VERSION 5.4 ;
NAMESCASESENSITIVE ON ;
BUSBITCHARS "[]" ;
DIVIDERCHAR "/" ;
UNITS
  DATABASE MICRONS 2000 ;
END UNITS
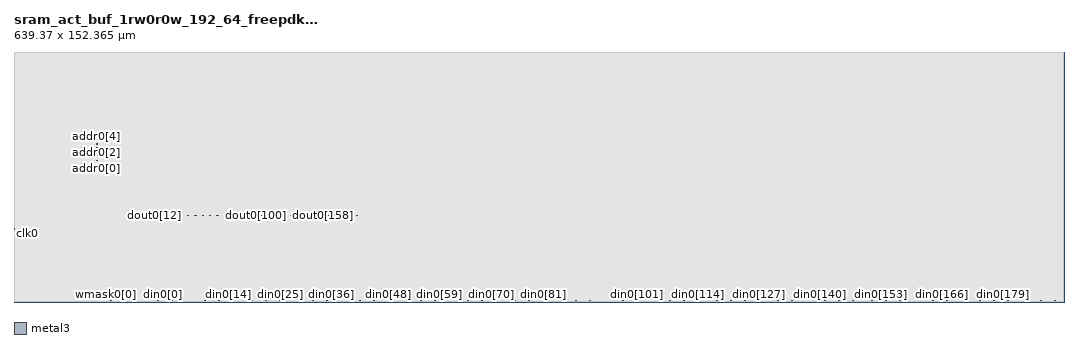
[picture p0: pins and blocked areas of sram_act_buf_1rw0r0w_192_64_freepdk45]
MACRO sram_act_buf_1rw0r0w_192_64_freepdk45
   CLASS BLOCK ;
   SIZE 639.37 BY 152.365 ;
   SYMMETRY X Y R90 ;
   PIN din0[0]
      DIRECTION INPUT ;
      PORT
         LAYER metal3 ;
         RECT  90.465 1.0375 90.6 1.1725 ;
      END
   END din0[0]
   PIN din0[1]
      DIRECTION INPUT ;
      PORT
         LAYER metal3 ;
         RECT  93.325 1.0375 93.46 1.1725 ;
      END
   END din0[1]
   PIN din0[2]
      DIRECTION INPUT ;
      PORT
         LAYER metal3 ;
         RECT  96.185 1.0375 96.32 1.1725 ;
      END
   END din0[2]
   PIN din0[3]
      DIRECTION INPUT ;
      PORT
         LAYER metal3 ;
         RECT  99.045 1.0375 99.18 1.1725 ;
      END
   END din0[3]
   PIN din0[4]
      DIRECTION INPUT ;
      PORT
         LAYER metal3 ;
         RECT  101.905 1.0375 102.04 1.1725 ;
      END
   END din0[4]
   PIN din0[5]
      DIRECTION INPUT ;
      PORT
         LAYER metal3 ;
         RECT  104.765 1.0375 104.9 1.1725 ;
      END
   END din0[5]
   PIN din0[6]
      DIRECTION INPUT ;
      PORT
         LAYER metal3 ;
         RECT  107.625 1.0375 107.76 1.1725 ;
      END
   END din0[6]
   PIN din0[7]
      DIRECTION INPUT ;
      PORT
         LAYER metal3 ;
         RECT  110.485 1.0375 110.62 1.1725 ;
      END
   END din0[7]
   PIN din0[8]
      DIRECTION INPUT ;
      PORT
         LAYER metal3 ;
         RECT  113.345 1.0375 113.48 1.1725 ;
      END
   END din0[8]
   PIN din0[9]
      DIRECTION INPUT ;
      PORT
         LAYER metal3 ;
         RECT  116.205 1.0375 116.34 1.1725 ;
      END
   END din0[9]
   PIN din0[10]
      DIRECTION INPUT ;
      PORT
         LAYER metal3 ;
         RECT  119.065 1.0375 119.2 1.1725 ;
      END
   END din0[10]
   PIN din0[11]
      DIRECTION INPUT ;
      PORT
         LAYER metal3 ;
         RECT  121.925 1.0375 122.06 1.1725 ;
      END
   END din0[11]
   PIN din0[12]
      DIRECTION INPUT ;
      PORT
         LAYER metal3 ;
         RECT  124.785 1.0375 124.92 1.1725 ;
      END
   END din0[12]
   PIN din0[13]
      DIRECTION INPUT ;
      PORT
         LAYER metal3 ;
         RECT  127.645 1.0375 127.78 1.1725 ;
      END
   END din0[13]
   PIN din0[14]
      DIRECTION INPUT ;
      PORT
         LAYER metal3 ;
         RECT  130.505 1.0375 130.64 1.1725 ;
      END
   END din0[14]
   PIN din0[15]
      DIRECTION INPUT ;
      PORT
         LAYER metal3 ;
         RECT  133.365 1.0375 133.5 1.1725 ;
      END
   END din0[15]
   PIN din0[16]
      DIRECTION INPUT ;
      PORT
         LAYER metal3 ;
         RECT  136.225 1.0375 136.36 1.1725 ;
      END
   END din0[16]
   PIN din0[17]
      DIRECTION INPUT ;
      PORT
         LAYER metal3 ;
         RECT  139.085 1.0375 139.22 1.1725 ;
      END
   END din0[17]
   PIN din0[18]
      DIRECTION INPUT ;
      PORT
         LAYER metal3 ;
         RECT  141.945 1.0375 142.08 1.1725 ;
      END
   END din0[18]
   PIN din0[19]
      DIRECTION INPUT ;
      PORT
         LAYER metal3 ;
         RECT  144.805 1.0375 144.94 1.1725 ;
      END
   END din0[19]
   PIN din0[20]
      DIRECTION INPUT ;
      PORT
         LAYER metal3 ;
         RECT  147.665 1.0375 147.8 1.1725 ;
      END
   END din0[20]
   PIN din0[21]
      DIRECTION INPUT ;
      PORT
         LAYER metal3 ;
         RECT  150.525 1.0375 150.66 1.1725 ;
      END
   END din0[21]
   PIN din0[22]
      DIRECTION INPUT ;
      PORT
         LAYER metal3 ;
         RECT  153.385 1.0375 153.52 1.1725 ;
      END
   END din0[22]
   PIN din0[23]
      DIRECTION INPUT ;
      PORT
         LAYER metal3 ;
         RECT  156.245 1.0375 156.38 1.1725 ;
      END
   END din0[23]
   PIN din0[24]
      DIRECTION INPUT ;
      PORT
         LAYER metal3 ;
         RECT  159.105 1.0375 159.24 1.1725 ;
      END
   END din0[24]
   PIN din0[25]
      DIRECTION INPUT ;
      PORT
         LAYER metal3 ;
         RECT  161.965 1.0375 162.1 1.1725 ;
      END
   END din0[25]
   PIN din0[26]
      DIRECTION INPUT ;
      PORT
         LAYER metal3 ;
         RECT  164.825 1.0375 164.96 1.1725 ;
      END
   END din0[26]
   PIN din0[27]
      DIRECTION INPUT ;
      PORT
         LAYER metal3 ;
         RECT  167.685 1.0375 167.82 1.1725 ;
      END
   END din0[27]
   PIN din0[28]
      DIRECTION INPUT ;
      PORT
         LAYER metal3 ;
         RECT  170.545 1.0375 170.68 1.1725 ;
      END
   END din0[28]
   PIN din0[29]
      DIRECTION INPUT ;
      PORT
         LAYER metal3 ;
         RECT  173.405 1.0375 173.54 1.1725 ;
      END
   END din0[29]
   PIN din0[30]
      DIRECTION INPUT ;
      PORT
         LAYER metal3 ;
         RECT  176.265 1.0375 176.4 1.1725 ;
      END
   END din0[30]
   PIN din0[31]
      DIRECTION INPUT ;
      PORT
         LAYER metal3 ;
         RECT  179.125 1.0375 179.26 1.1725 ;
      END
   END din0[31]
   PIN din0[32]
      DIRECTION INPUT ;
      PORT
         LAYER metal3 ;
         RECT  181.985 1.0375 182.12 1.1725 ;
      END
   END din0[32]
   PIN din0[33]
      DIRECTION INPUT ;
      PORT
         LAYER metal3 ;
         RECT  184.845 1.0375 184.98 1.1725 ;
      END
   END din0[33]
   PIN din0[34]
      DIRECTION INPUT ;
      PORT
         LAYER metal3 ;
         RECT  187.705 1.0375 187.84 1.1725 ;
      END
   END din0[34]
   PIN din0[35]
      DIRECTION INPUT ;
      PORT
         LAYER metal3 ;
         RECT  190.565 1.0375 190.7 1.1725 ;
      END
   END din0[35]
   PIN din0[36]
      DIRECTION INPUT ;
      PORT
         LAYER metal3 ;
         RECT  193.425 1.0375 193.56 1.1725 ;
      END
   END din0[36]
   PIN din0[37]
      DIRECTION INPUT ;
      PORT
         LAYER metal3 ;
         RECT  196.285 1.0375 196.42 1.1725 ;
      END
   END din0[37]
   PIN din0[38]
      DIRECTION INPUT ;
      PORT
         LAYER metal3 ;
         RECT  199.145 1.0375 199.28 1.1725 ;
      END
   END din0[38]
   PIN din0[39]
      DIRECTION INPUT ;
      PORT
         LAYER metal3 ;
         RECT  202.005 1.0375 202.14 1.1725 ;
      END
   END din0[39]
   PIN din0[40]
      DIRECTION INPUT ;
      PORT
         LAYER metal3 ;
         RECT  204.865 1.0375 205.0 1.1725 ;
      END
   END din0[40]
   PIN din0[41]
      DIRECTION INPUT ;
      PORT
         LAYER metal3 ;
         RECT  207.725 1.0375 207.86 1.1725 ;
      END
   END din0[41]
   PIN din0[42]
      DIRECTION INPUT ;
      PORT
         LAYER metal3 ;
         RECT  210.585 1.0375 210.72 1.1725 ;
      END
   END din0[42]
   PIN din0[43]
      DIRECTION INPUT ;
      PORT
         LAYER metal3 ;
         RECT  213.445 1.0375 213.58 1.1725 ;
      END
   END din0[43]
   PIN din0[44]
      DIRECTION INPUT ;
      PORT
         LAYER metal3 ;
         RECT  216.305 1.0375 216.44 1.1725 ;
      END
   END din0[44]
   PIN din0[45]
      DIRECTION INPUT ;
      PORT
         LAYER metal3 ;
         RECT  219.165 1.0375 219.3 1.1725 ;
      END
   END din0[45]
   PIN din0[46]
      DIRECTION INPUT ;
      PORT
         LAYER metal3 ;
         RECT  222.025 1.0375 222.16 1.1725 ;
      END
   END din0[46]
   PIN din0[47]
      DIRECTION INPUT ;
      PORT
         LAYER metal3 ;
         RECT  224.885 1.0375 225.02 1.1725 ;
      END
   END din0[47]
   PIN din0[48]
      DIRECTION INPUT ;
      PORT
         LAYER metal3 ;
         RECT  227.745 1.0375 227.88 1.1725 ;
      END
   END din0[48]
   PIN din0[49]
      DIRECTION INPUT ;
      PORT
         LAYER metal3 ;
         RECT  230.605 1.0375 230.74 1.1725 ;
      END
   END din0[49]
   PIN din0[50]
      DIRECTION INPUT ;
      PORT
         LAYER metal3 ;
         RECT  233.465 1.0375 233.6 1.1725 ;
      END
   END din0[50]
   PIN din0[51]
      DIRECTION INPUT ;
      PORT
         LAYER metal3 ;
         RECT  236.325 1.0375 236.46 1.1725 ;
      END
   END din0[51]
   PIN din0[52]
      DIRECTION INPUT ;
      PORT
         LAYER metal3 ;
         RECT  239.185 1.0375 239.32 1.1725 ;
      END
   END din0[52]
   PIN din0[53]
      DIRECTION INPUT ;
      PORT
         LAYER metal3 ;
         RECT  242.045 1.0375 242.18 1.1725 ;
      END
   END din0[53]
   PIN din0[54]
      DIRECTION INPUT ;
      PORT
         LAYER metal3 ;
         RECT  244.905 1.0375 245.04 1.1725 ;
      END
   END din0[54]
   PIN din0[55]
      DIRECTION INPUT ;
      PORT
         LAYER metal3 ;
         RECT  247.765 1.0375 247.9 1.1725 ;
      END
   END din0[55]
   PIN din0[56]
      DIRECTION INPUT ;
      PORT
         LAYER metal3 ;
         RECT  250.625 1.0375 250.76 1.1725 ;
      END
   END din0[56]
   PIN din0[57]
      DIRECTION INPUT ;
      PORT
         LAYER metal3 ;
         RECT  253.485 1.0375 253.62 1.1725 ;
      END
   END din0[57]
   PIN din0[58]
      DIRECTION INPUT ;
      PORT
         LAYER metal3 ;
         RECT  256.345 1.0375 256.48 1.1725 ;
      END
   END din0[58]
   PIN din0[59]
      DIRECTION INPUT ;
      PORT
         LAYER metal3 ;
         RECT  259.205 1.0375 259.34 1.1725 ;
      END
   END din0[59]
   PIN din0[60]
      DIRECTION INPUT ;
      PORT
         LAYER metal3 ;
         RECT  262.065 1.0375 262.2 1.1725 ;
      END
   END din0[60]
   PIN din0[61]
      DIRECTION INPUT ;
      PORT
         LAYER metal3 ;
         RECT  264.925 1.0375 265.06 1.1725 ;
      END
   END din0[61]
   PIN din0[62]
      DIRECTION INPUT ;
      PORT
         LAYER metal3 ;
         RECT  267.785 1.0375 267.92 1.1725 ;
      END
   END din0[62]
   PIN din0[63]
      DIRECTION INPUT ;
      PORT
         LAYER metal3 ;
         RECT  270.645 1.0375 270.78 1.1725 ;
      END
   END din0[63]
   PIN din0[64]
      DIRECTION INPUT ;
      PORT
         LAYER metal3 ;
         RECT  273.505 1.0375 273.64 1.1725 ;
      END
   END din0[64]
   PIN din0[65]
      DIRECTION INPUT ;
      PORT
         LAYER metal3 ;
         RECT  276.365 1.0375 276.5 1.1725 ;
      END
   END din0[65]
   PIN din0[66]
      DIRECTION INPUT ;
      PORT
         LAYER metal3 ;
         RECT  279.225 1.0375 279.36 1.1725 ;
      END
   END din0[66]
   PIN din0[67]
      DIRECTION INPUT ;
      PORT
         LAYER metal3 ;
         RECT  282.085 1.0375 282.22 1.1725 ;
      END
   END din0[67]
   PIN din0[68]
      DIRECTION INPUT ;
      PORT
         LAYER metal3 ;
         RECT  284.945 1.0375 285.08 1.1725 ;
      END
   END din0[68]
   PIN din0[69]
      DIRECTION INPUT ;
      PORT
         LAYER metal3 ;
         RECT  287.805 1.0375 287.94 1.1725 ;
      END
   END din0[69]
   PIN din0[70]
      DIRECTION INPUT ;
      PORT
         LAYER metal3 ;
         RECT  290.665 1.0375 290.8 1.1725 ;
      END
   END din0[70]
   PIN din0[71]
      DIRECTION INPUT ;
      PORT
         LAYER metal3 ;
         RECT  293.525 1.0375 293.66 1.1725 ;
      END
   END din0[71]
   PIN din0[72]
      DIRECTION INPUT ;
      PORT
         LAYER metal3 ;
         RECT  296.385 1.0375 296.52 1.1725 ;
      END
   END din0[72]
   PIN din0[73]
      DIRECTION INPUT ;
      PORT
         LAYER metal3 ;
         RECT  299.245 1.0375 299.38 1.1725 ;
      END
   END din0[73]
   PIN din0[74]
      DIRECTION INPUT ;
      PORT
         LAYER metal3 ;
         RECT  302.105 1.0375 302.24 1.1725 ;
      END
   END din0[74]
   PIN din0[75]
      DIRECTION INPUT ;
      PORT
         LAYER metal3 ;
         RECT  304.965 1.0375 305.1 1.1725 ;
      END
   END din0[75]
   PIN din0[76]
      DIRECTION INPUT ;
      PORT
         LAYER metal3 ;
         RECT  307.825 1.0375 307.96 1.1725 ;
      END
   END din0[76]
   PIN din0[77]
      DIRECTION INPUT ;
      PORT
         LAYER metal3 ;
         RECT  310.685 1.0375 310.82 1.1725 ;
      END
   END din0[77]
   PIN din0[78]
      DIRECTION INPUT ;
      PORT
         LAYER metal3 ;
         RECT  313.545 1.0375 313.68 1.1725 ;
      END
   END din0[78]
   PIN din0[79]
      DIRECTION INPUT ;
      PORT
         LAYER metal3 ;
         RECT  316.405 1.0375 316.54 1.1725 ;
      END
   END din0[79]
   PIN din0[80]
      DIRECTION INPUT ;
      PORT
         LAYER metal3 ;
         RECT  319.265 1.0375 319.4 1.1725 ;
      END
   END din0[80]
   PIN din0[81]
      DIRECTION INPUT ;
      PORT
         LAYER metal3 ;
         RECT  322.125 1.0375 322.26 1.1725 ;
      END
   END din0[81]
   PIN din0[82]
      DIRECTION INPUT ;
      PORT
         LAYER metal3 ;
         RECT  324.985 1.0375 325.12 1.1725 ;
      END
   END din0[82]
   PIN din0[83]
      DIRECTION INPUT ;
      PORT
         LAYER metal3 ;
         RECT  327.845 1.0375 327.98 1.1725 ;
      END
   END din0[83]
   PIN din0[84]
      DIRECTION INPUT ;
      PORT
         LAYER metal3 ;
         RECT  330.705 1.0375 330.84 1.1725 ;
      END
   END din0[84]
   PIN din0[85]
      DIRECTION INPUT ;
      PORT
         LAYER metal3 ;
         RECT  333.565 1.0375 333.7 1.1725 ;
      END
   END din0[85]
   PIN din0[86]
      DIRECTION INPUT ;
      PORT
         LAYER metal3 ;
         RECT  336.425 1.0375 336.56 1.1725 ;
      END
   END din0[86]
   PIN din0[87]
      DIRECTION INPUT ;
      PORT
         LAYER metal3 ;
         RECT  339.285 1.0375 339.42 1.1725 ;
      END
   END din0[87]
   PIN din0[88]
      DIRECTION INPUT ;
      PORT
         LAYER metal3 ;
         RECT  342.145 1.0375 342.28 1.1725 ;
      END
   END din0[88]
   PIN din0[89]
      DIRECTION INPUT ;
      PORT
         LAYER metal3 ;
         RECT  345.005 1.0375 345.14 1.1725 ;
      END
   END din0[89]
   PIN din0[90]
      DIRECTION INPUT ;
      PORT
         LAYER metal3 ;
         RECT  347.865 1.0375 348.0 1.1725 ;
      END
   END din0[90]
   PIN din0[91]
      DIRECTION INPUT ;
      PORT
         LAYER metal3 ;
         RECT  350.725 1.0375 350.86 1.1725 ;
      END
   END din0[91]
   PIN din0[92]
      DIRECTION INPUT ;
      PORT
         LAYER metal3 ;
         RECT  353.585 1.0375 353.72 1.1725 ;
      END
   END din0[92]
   PIN din0[93]
      DIRECTION INPUT ;
      PORT
         LAYER metal3 ;
         RECT  356.445 1.0375 356.58 1.1725 ;
      END
   END din0[93]
   PIN din0[94]
      DIRECTION INPUT ;
      PORT
         LAYER metal3 ;
         RECT  359.305 1.0375 359.44 1.1725 ;
      END
   END din0[94]
   PIN din0[95]
      DIRECTION INPUT ;
      PORT
         LAYER metal3 ;
         RECT  362.165 1.0375 362.3 1.1725 ;
      END
   END din0[95]
   PIN din0[96]
      DIRECTION INPUT ;
      PORT
         LAYER metal3 ;
         RECT  365.025 1.0375 365.16 1.1725 ;
      END
   END din0[96]
   PIN din0[97]
      DIRECTION INPUT ;
      PORT
         LAYER metal3 ;
         RECT  367.885 1.0375 368.02 1.1725 ;
      END
   END din0[97]
   PIN din0[98]
      DIRECTION INPUT ;
      PORT
         LAYER metal3 ;
         RECT  370.745 1.0375 370.88 1.1725 ;
      END
   END din0[98]
   PIN din0[99]
      DIRECTION INPUT ;
      PORT
         LAYER metal3 ;
         RECT  373.605 1.0375 373.74 1.1725 ;
      END
   END din0[99]
   PIN din0[100]
      DIRECTION INPUT ;
      PORT
         LAYER metal3 ;
         RECT  376.465 1.0375 376.6 1.1725 ;
      END
   END din0[100]
   PIN din0[101]
      DIRECTION INPUT ;
      PORT
         LAYER metal3 ;
         RECT  379.325 1.0375 379.46 1.1725 ;
      END
   END din0[101]
   PIN din0[102]
      DIRECTION INPUT ;
      PORT
         LAYER metal3 ;
         RECT  382.185 1.0375 382.32 1.1725 ;
      END
   END din0[102]
   PIN din0[103]
      DIRECTION INPUT ;
      PORT
         LAYER metal3 ;
         RECT  385.045 1.0375 385.18 1.1725 ;
      END
   END din0[103]
   PIN din0[104]
      DIRECTION INPUT ;
      PORT
         LAYER metal3 ;
         RECT  387.905 1.0375 388.04 1.1725 ;
      END
   END din0[104]
   PIN din0[105]
      DIRECTION INPUT ;
      PORT
         LAYER metal3 ;
         RECT  390.765 1.0375 390.9 1.1725 ;
      END
   END din0[105]
   PIN din0[106]
      DIRECTION INPUT ;
      PORT
         LAYER metal3 ;
         RECT  393.625 1.0375 393.76 1.1725 ;
      END
   END din0[106]
   PIN din0[107]
      DIRECTION INPUT ;
      PORT
         LAYER metal3 ;
         RECT  396.485 1.0375 396.62 1.1725 ;
      END
   END din0[107]
   PIN din0[108]
      DIRECTION INPUT ;
      PORT
         LAYER metal3 ;
         RECT  399.345 1.0375 399.48 1.1725 ;
      END
   END din0[108]
   PIN din0[109]
      DIRECTION INPUT ;
      PORT
         LAYER metal3 ;
         RECT  402.205 1.0375 402.34 1.1725 ;
      END
   END din0[109]
   PIN din0[110]
      DIRECTION INPUT ;
      PORT
         LAYER metal3 ;
         RECT  405.065 1.0375 405.2 1.1725 ;
      END
   END din0[110]
   PIN din0[111]
      DIRECTION INPUT ;
      PORT
         LAYER metal3 ;
         RECT  407.925 1.0375 408.06 1.1725 ;
      END
   END din0[111]
   PIN din0[112]
      DIRECTION INPUT ;
      PORT
         LAYER metal3 ;
         RECT  410.785 1.0375 410.92 1.1725 ;
      END
   END din0[112]
   PIN din0[113]
      DIRECTION INPUT ;
      PORT
         LAYER metal3 ;
         RECT  413.645 1.0375 413.78 1.1725 ;
      END
   END din0[113]
   PIN din0[114]
      DIRECTION INPUT ;
      PORT
         LAYER metal3 ;
         RECT  416.505 1.0375 416.64 1.1725 ;
      END
   END din0[114]
   PIN din0[115]
      DIRECTION INPUT ;
      PORT
         LAYER metal3 ;
         RECT  419.365 1.0375 419.5 1.1725 ;
      END
   END din0[115]
   PIN din0[116]
      DIRECTION INPUT ;
      PORT
         LAYER metal3 ;
         RECT  422.225 1.0375 422.36 1.1725 ;
      END
   END din0[116]
   PIN din0[117]
      DIRECTION INPUT ;
      PORT
         LAYER metal3 ;
         RECT  425.085 1.0375 425.22 1.1725 ;
      END
   END din0[117]
   PIN din0[118]
      DIRECTION INPUT ;
      PORT
         LAYER metal3 ;
         RECT  427.945 1.0375 428.08 1.1725 ;
      END
   END din0[118]
   PIN din0[119]
      DIRECTION INPUT ;
      PORT
         LAYER metal3 ;
         RECT  430.805 1.0375 430.94 1.1725 ;
      END
   END din0[119]
   PIN din0[120]
      DIRECTION INPUT ;
      PORT
         LAYER metal3 ;
         RECT  433.665 1.0375 433.8 1.1725 ;
      END
   END din0[120]
   PIN din0[121]
      DIRECTION INPUT ;
      PORT
         LAYER metal3 ;
         RECT  436.525 1.0375 436.66 1.1725 ;
      END
   END din0[121]
   PIN din0[122]
      DIRECTION INPUT ;
      PORT
         LAYER metal3 ;
         RECT  439.385 1.0375 439.52 1.1725 ;
      END
   END din0[122]
   PIN din0[123]
      DIRECTION INPUT ;
      PORT
         LAYER metal3 ;
         RECT  442.245 1.0375 442.38 1.1725 ;
      END
   END din0[123]
   PIN din0[124]
      DIRECTION INPUT ;
      PORT
         LAYER metal3 ;
         RECT  445.105 1.0375 445.24 1.1725 ;
      END
   END din0[124]
   PIN din0[125]
      DIRECTION INPUT ;
      PORT
         LAYER metal3 ;
         RECT  447.965 1.0375 448.1 1.1725 ;
      END
   END din0[125]
   PIN din0[126]
      DIRECTION INPUT ;
      PORT
         LAYER metal3 ;
         RECT  450.825 1.0375 450.96 1.1725 ;
      END
   END din0[126]
   PIN din0[127]
      DIRECTION INPUT ;
      PORT
         LAYER metal3 ;
         RECT  453.685 1.0375 453.82 1.1725 ;
      END
   END din0[127]
   PIN din0[128]
      DIRECTION INPUT ;
      PORT
         LAYER metal3 ;
         RECT  456.545 1.0375 456.68 1.1725 ;
      END
   END din0[128]
   PIN din0[129]
      DIRECTION INPUT ;
      PORT
         LAYER metal3 ;
         RECT  459.405 1.0375 459.54 1.1725 ;
      END
   END din0[129]
   PIN din0[130]
      DIRECTION INPUT ;
      PORT
         LAYER metal3 ;
         RECT  462.265 1.0375 462.4 1.1725 ;
      END
   END din0[130]
   PIN din0[131]
      DIRECTION INPUT ;
      PORT
         LAYER metal3 ;
         RECT  465.125 1.0375 465.26 1.1725 ;
      END
   END din0[131]
   PIN din0[132]
      DIRECTION INPUT ;
      PORT
         LAYER metal3 ;
         RECT  467.985 1.0375 468.12 1.1725 ;
      END
   END din0[132]
   PIN din0[133]
      DIRECTION INPUT ;
      PORT
         LAYER metal3 ;
         RECT  470.845 1.0375 470.98 1.1725 ;
      END
   END din0[133]
   PIN din0[134]
      DIRECTION INPUT ;
      PORT
         LAYER metal3 ;
         RECT  473.705 1.0375 473.84 1.1725 ;
      END
   END din0[134]
   PIN din0[135]
      DIRECTION INPUT ;
      PORT
         LAYER metal3 ;
         RECT  476.565 1.0375 476.7 1.1725 ;
      END
   END din0[135]
   PIN din0[136]
      DIRECTION INPUT ;
      PORT
         LAYER metal3 ;
         RECT  479.425 1.0375 479.56 1.1725 ;
      END
   END din0[136]
   PIN din0[137]
      DIRECTION INPUT ;
      PORT
         LAYER metal3 ;
         RECT  482.285 1.0375 482.42 1.1725 ;
      END
   END din0[137]
   PIN din0[138]
      DIRECTION INPUT ;
      PORT
         LAYER metal3 ;
         RECT  485.145 1.0375 485.28 1.1725 ;
      END
   END din0[138]
   PIN din0[139]
      DIRECTION INPUT ;
      PORT
         LAYER metal3 ;
         RECT  488.005 1.0375 488.14 1.1725 ;
      END
   END din0[139]
   PIN din0[140]
      DIRECTION INPUT ;
      PORT
         LAYER metal3 ;
         RECT  490.865 1.0375 491.0 1.1725 ;
      END
   END din0[140]
   PIN din0[141]
      DIRECTION INPUT ;
      PORT
         LAYER metal3 ;
         RECT  493.725 1.0375 493.86 1.1725 ;
      END
   END din0[141]
   PIN din0[142]
      DIRECTION INPUT ;
      PORT
         LAYER metal3 ;
         RECT  496.585 1.0375 496.72 1.1725 ;
      END
   END din0[142]
   PIN din0[143]
      DIRECTION INPUT ;
      PORT
         LAYER metal3 ;
         RECT  499.445 1.0375 499.58 1.1725 ;
      END
   END din0[143]
   PIN din0[144]
      DIRECTION INPUT ;
      PORT
         LAYER metal3 ;
         RECT  502.305 1.0375 502.44 1.1725 ;
      END
   END din0[144]
   PIN din0[145]
      DIRECTION INPUT ;
      PORT
         LAYER metal3 ;
         RECT  505.165 1.0375 505.3 1.1725 ;
      END
   END din0[145]
   PIN din0[146]
      DIRECTION INPUT ;
      PORT
         LAYER metal3 ;
         RECT  508.025 1.0375 508.16 1.1725 ;
      END
   END din0[146]
   PIN din0[147]
      DIRECTION INPUT ;
      PORT
         LAYER metal3 ;
         RECT  510.885 1.0375 511.02 1.1725 ;
      END
   END din0[147]
   PIN din0[148]
      DIRECTION INPUT ;
      PORT
         LAYER metal3 ;
         RECT  513.745 1.0375 513.88 1.1725 ;
      END
   END din0[148]
   PIN din0[149]
      DIRECTION INPUT ;
      PORT
         LAYER metal3 ;
         RECT  516.605 1.0375 516.74 1.1725 ;
      END
   END din0[149]
   PIN din0[150]
      DIRECTION INPUT ;
      PORT
         LAYER metal3 ;
         RECT  519.465 1.0375 519.6 1.1725 ;
      END
   END din0[150]
   PIN din0[151]
      DIRECTION INPUT ;
      PORT
         LAYER metal3 ;
         RECT  522.325 1.0375 522.46 1.1725 ;
      END
   END din0[151]
   PIN din0[152]
      DIRECTION INPUT ;
      PORT
         LAYER metal3 ;
         RECT  525.185 1.0375 525.32 1.1725 ;
      END
   END din0[152]
   PIN din0[153]
      DIRECTION INPUT ;
      PORT
         LAYER metal3 ;
         RECT  528.045 1.0375 528.18 1.1725 ;
      END
   END din0[153]
   PIN din0[154]
      DIRECTION INPUT ;
      PORT
         LAYER metal3 ;
         RECT  530.905 1.0375 531.04 1.1725 ;
      END
   END din0[154]
   PIN din0[155]
      DIRECTION INPUT ;
      PORT
         LAYER metal3 ;
         RECT  533.765 1.0375 533.9 1.1725 ;
      END
   END din0[155]
   PIN din0[156]
      DIRECTION INPUT ;
      PORT
         LAYER metal3 ;
         RECT  536.625 1.0375 536.76 1.1725 ;
      END
   END din0[156]
   PIN din0[157]
      DIRECTION INPUT ;
      PORT
         LAYER metal3 ;
         RECT  539.485 1.0375 539.62 1.1725 ;
      END
   END din0[157]
   PIN din0[158]
      DIRECTION INPUT ;
      PORT
         LAYER metal3 ;
         RECT  542.345 1.0375 542.48 1.1725 ;
      END
   END din0[158]
   PIN din0[159]
      DIRECTION INPUT ;
      PORT
         LAYER metal3 ;
         RECT  545.205 1.0375 545.34 1.1725 ;
      END
   END din0[159]
   PIN din0[160]
      DIRECTION INPUT ;
      PORT
         LAYER metal3 ;
         RECT  548.065 1.0375 548.2 1.1725 ;
      END
   END din0[160]
   PIN din0[161]
      DIRECTION INPUT ;
      PORT
         LAYER metal3 ;
         RECT  550.925 1.0375 551.06 1.1725 ;
      END
   END din0[161]
   PIN din0[162]
      DIRECTION INPUT ;
      PORT
         LAYER metal3 ;
         RECT  553.785 1.0375 553.92 1.1725 ;
      END
   END din0[162]
   PIN din0[163]
      DIRECTION INPUT ;
      PORT
         LAYER metal3 ;
         RECT  556.645 1.0375 556.78 1.1725 ;
      END
   END din0[163]
   PIN din0[164]
      DIRECTION INPUT ;
      PORT
         LAYER metal3 ;
         RECT  559.505 1.0375 559.64 1.1725 ;
      END
   END din0[164]
   PIN din0[165]
      DIRECTION INPUT ;
      PORT
         LAYER metal3 ;
         RECT  562.365 1.0375 562.5 1.1725 ;
      END
   END din0[165]
   PIN din0[166]
      DIRECTION INPUT ;
      PORT
         LAYER metal3 ;
         RECT  565.225 1.0375 565.36 1.1725 ;
      END
   END din0[166]
   PIN din0[167]
      DIRECTION INPUT ;
      PORT
         LAYER metal3 ;
         RECT  568.085 1.0375 568.22 1.1725 ;
      END
   END din0[167]
   PIN din0[168]
      DIRECTION INPUT ;
      PORT
         LAYER metal3 ;
         RECT  570.945 1.0375 571.08 1.1725 ;
      END
   END din0[168]
   PIN din0[169]
      DIRECTION INPUT ;
      PORT
         LAYER metal3 ;
         RECT  573.805 1.0375 573.94 1.1725 ;
      END
   END din0[169]
   PIN din0[170]
      DIRECTION INPUT ;
      PORT
         LAYER metal3 ;
         RECT  576.665 1.0375 576.8 1.1725 ;
      END
   END din0[170]
   PIN din0[171]
      DIRECTION INPUT ;
      PORT
         LAYER metal3 ;
         RECT  579.525 1.0375 579.66 1.1725 ;
      END
   END din0[171]
   PIN din0[172]
      DIRECTION INPUT ;
      PORT
         LAYER metal3 ;
         RECT  582.385 1.0375 582.52 1.1725 ;
      END
   END din0[172]
   PIN din0[173]
      DIRECTION INPUT ;
      PORT
         LAYER metal3 ;
         RECT  585.245 1.0375 585.38 1.1725 ;
      END
   END din0[173]
   PIN din0[174]
      DIRECTION INPUT ;
      PORT
         LAYER metal3 ;
         RECT  588.105 1.0375 588.24 1.1725 ;
      END
   END din0[174]
   PIN din0[175]
      DIRECTION INPUT ;
      PORT
         LAYER metal3 ;
         RECT  590.965 1.0375 591.1 1.1725 ;
      END
   END din0[175]
   PIN din0[176]
      DIRECTION INPUT ;
      PORT
         LAYER metal3 ;
         RECT  593.825 1.0375 593.96 1.1725 ;
      END
   END din0[176]
   PIN din0[177]
      DIRECTION INPUT ;
      PORT
         LAYER metal3 ;
         RECT  596.685 1.0375 596.82 1.1725 ;
      END
   END din0[177]
   PIN din0[178]
      DIRECTION INPUT ;
      PORT
         LAYER metal3 ;
         RECT  599.545 1.0375 599.68 1.1725 ;
      END
   END din0[178]
   PIN din0[179]
      DIRECTION INPUT ;
      PORT
         LAYER metal3 ;
         RECT  602.405 1.0375 602.54 1.1725 ;
      END
   END din0[179]
   PIN din0[180]
      DIRECTION INPUT ;
      PORT
         LAYER metal3 ;
         RECT  605.265 1.0375 605.4 1.1725 ;
      END
   END din0[180]
   PIN din0[181]
      DIRECTION INPUT ;
      PORT
         LAYER metal3 ;
         RECT  608.125 1.0375 608.26 1.1725 ;
      END
   END din0[181]
   PIN din0[182]
      DIRECTION INPUT ;
      PORT
         LAYER metal3 ;
         RECT  610.985 1.0375 611.12 1.1725 ;
      END
   END din0[182]
   PIN din0[183]
      DIRECTION INPUT ;
      PORT
         LAYER metal3 ;
         RECT  613.845 1.0375 613.98 1.1725 ;
      END
   END din0[183]
   PIN din0[184]
      DIRECTION INPUT ;
      PORT
         LAYER metal3 ;
         RECT  616.705 1.0375 616.84 1.1725 ;
      END
   END din0[184]
   PIN din0[185]
      DIRECTION INPUT ;
      PORT
         LAYER metal3 ;
         RECT  619.565 1.0375 619.7 1.1725 ;
      END
   END din0[185]
   PIN din0[186]
      DIRECTION INPUT ;
      PORT
         LAYER metal3 ;
         RECT  622.425 1.0375 622.56 1.1725 ;
      END
   END din0[186]
   PIN din0[187]
      DIRECTION INPUT ;
      PORT
         LAYER metal3 ;
         RECT  625.285 1.0375 625.42 1.1725 ;
      END
   END din0[187]
   PIN din0[188]
      DIRECTION INPUT ;
      PORT
         LAYER metal3 ;
         RECT  628.145 1.0375 628.28 1.1725 ;
      END
   END din0[188]
   PIN din0[189]
      DIRECTION INPUT ;
      PORT
         LAYER metal3 ;
         RECT  631.005 1.0375 631.14 1.1725 ;
      END
   END din0[189]
   PIN din0[190]
      DIRECTION INPUT ;
      PORT
         LAYER metal3 ;
         RECT  633.865 1.0375 634.0 1.1725 ;
      END
   END din0[190]
   PIN din0[191]
      DIRECTION INPUT ;
      PORT
         LAYER metal3 ;
         RECT  636.725 1.0375 636.86 1.1725 ;
      END
   END din0[191]
   PIN addr0[0]
      DIRECTION INPUT ;
      PORT
         LAYER metal3 ;
         RECT  50.425 86.32 50.56 86.455 ;
      END
   END addr0[0]
   PIN addr0[1]
      DIRECTION INPUT ;
      PORT
         LAYER metal3 ;
         RECT  50.425 89.05 50.56 89.185 ;
      END
   END addr0[1]
   PIN addr0[2]
      DIRECTION INPUT ;
      PORT
         LAYER metal3 ;
         RECT  50.425 91.26 50.56 91.395 ;
      END
   END addr0[2]
   PIN addr0[3]
      DIRECTION INPUT ;
      PORT
         LAYER metal3 ;
         RECT  50.425 93.99 50.56 94.125 ;
      END
   END addr0[3]
   PIN addr0[4]
      DIRECTION INPUT ;
      PORT
         LAYER metal3 ;
         RECT  50.425 96.2 50.56 96.335 ;
      END
   END addr0[4]
   PIN addr0[5]
      DIRECTION INPUT ;
      PORT
         LAYER metal3 ;
         RECT  50.425 98.93 50.56 99.065 ;
      END
   END addr0[5]
   PIN csb0
      DIRECTION INPUT ;
      PORT
         LAYER metal3 ;
         RECT  0.285 41.6 0.42 41.735 ;
      END
   END csb0
   PIN web0
      DIRECTION INPUT ;
      PORT
         LAYER metal3 ;
         RECT  0.285 44.33 0.42 44.465 ;
      END
   END web0
   PIN clk0
      DIRECTION INPUT ;
      PORT
         LAYER metal3 ;
         RECT  6.5275 41.685 6.6625 41.82 ;
      END
   END clk0
   PIN wmask0[0]
      DIRECTION INPUT ;
      PORT
         LAYER metal3 ;
         RECT  56.145 1.0375 56.28 1.1725 ;
      END
   END wmask0[0]
   PIN wmask0[1]
      DIRECTION INPUT ;
      PORT
         LAYER metal3 ;
         RECT  59.005 1.0375 59.14 1.1725 ;
      END
   END wmask0[1]
   PIN wmask0[2]
      DIRECTION INPUT ;
      PORT
         LAYER metal3 ;
         RECT  61.865 1.0375 62.0 1.1725 ;
      END
   END wmask0[2]
   PIN wmask0[3]
      DIRECTION INPUT ;
      PORT
         LAYER metal3 ;
         RECT  64.725 1.0375 64.86 1.1725 ;
      END
   END wmask0[3]
   PIN wmask0[4]
      DIRECTION INPUT ;
      PORT
         LAYER metal3 ;
         RECT  67.585 1.0375 67.72 1.1725 ;
      END
   END wmask0[4]
   PIN wmask0[5]
      DIRECTION INPUT ;
      PORT
         LAYER metal3 ;
         RECT  70.445 1.0375 70.58 1.1725 ;
      END
   END wmask0[5]
   PIN wmask0[6]
      DIRECTION INPUT ;
      PORT
         LAYER metal3 ;
         RECT  73.305 1.0375 73.44 1.1725 ;
      END
   END wmask0[6]
   PIN wmask0[7]
      DIRECTION INPUT ;
      PORT
         LAYER metal3 ;
         RECT  76.165 1.0375 76.3 1.1725 ;
      END
   END wmask0[7]
   PIN wmask0[8]
      DIRECTION INPUT ;
      PORT
         LAYER metal3 ;
         RECT  79.025 1.0375 79.16 1.1725 ;
      END
   END wmask0[8]
   PIN wmask0[9]
      DIRECTION INPUT ;
      PORT
         LAYER metal3 ;
         RECT  81.885 1.0375 82.02 1.1725 ;
      END
   END wmask0[9]
   PIN wmask0[10]
      DIRECTION INPUT ;
      PORT
         LAYER metal3 ;
         RECT  84.745 1.0375 84.88 1.1725 ;
      END
   END wmask0[10]
   PIN wmask0[11]
      DIRECTION INPUT ;
      PORT
         LAYER metal3 ;
         RECT  87.605 1.0375 87.74 1.1725 ;
      END
   END wmask0[11]
   PIN dout0[0]
      DIRECTION OUTPUT ;
      PORT
         LAYER metal3 ;
         RECT  76.955 52.7425 77.09 52.8775 ;
      END
   END dout0[0]
   PIN dout0[1]
      DIRECTION OUTPUT ;
      PORT
         LAYER metal3 ;
         RECT  77.66 52.7425 77.795 52.8775 ;
      END
   END dout0[1]
   PIN dout0[2]
      DIRECTION OUTPUT ;
      PORT
         LAYER metal3 ;
         RECT  78.365 52.7425 78.5 52.8775 ;
      END
   END dout0[2]
   PIN dout0[3]
      DIRECTION OUTPUT ;
      PORT
         LAYER metal3 ;
         RECT  79.07 52.7425 79.205 52.8775 ;
      END
   END dout0[3]
   PIN dout0[4]
      DIRECTION OUTPUT ;
      PORT
         LAYER metal3 ;
         RECT  79.775 52.7425 79.91 52.8775 ;
      END
   END dout0[4]
   PIN dout0[5]
      DIRECTION OUTPUT ;
      PORT
         LAYER metal3 ;
         RECT  80.48 52.7425 80.615 52.8775 ;
      END
   END dout0[5]
   PIN dout0[6]
      DIRECTION OUTPUT ;
      PORT
         LAYER metal3 ;
         RECT  81.185 52.7425 81.32 52.8775 ;
      END
   END dout0[6]
   PIN dout0[7]
      DIRECTION OUTPUT ;
      PORT
         LAYER metal3 ;
         RECT  81.89 52.7425 82.025 52.8775 ;
      END
   END dout0[7]
   PIN dout0[8]
      DIRECTION OUTPUT ;
      PORT
         LAYER metal3 ;
         RECT  82.595 52.7425 82.73 52.8775 ;
      END
   END dout0[8]
   PIN dout0[9]
      DIRECTION OUTPUT ;
      PORT
         LAYER metal3 ;
         RECT  83.3 52.7425 83.435 52.8775 ;
      END
   END dout0[9]
   PIN dout0[10]
      DIRECTION OUTPUT ;
      PORT
         LAYER metal3 ;
         RECT  84.005 52.7425 84.14 52.8775 ;
      END
   END dout0[10]
   PIN dout0[11]
      DIRECTION OUTPUT ;
      PORT
         LAYER metal3 ;
         RECT  84.71 52.7425 84.845 52.8775 ;
      END
   END dout0[11]
   PIN dout0[12]
      DIRECTION OUTPUT ;
      PORT
         LAYER metal3 ;
         RECT  85.415 52.7425 85.55 52.8775 ;
      END
   END dout0[12]
   PIN dout0[13]
      DIRECTION OUTPUT ;
      PORT
         LAYER metal3 ;
         RECT  86.12 52.7425 86.255 52.8775 ;
      END
   END dout0[13]
   PIN dout0[14]
      DIRECTION OUTPUT ;
      PORT
         LAYER metal3 ;
         RECT  86.825 52.7425 86.96 52.8775 ;
      END
   END dout0[14]
   PIN dout0[15]
      DIRECTION OUTPUT ;
      PORT
         LAYER metal3 ;
         RECT  87.53 52.7425 87.665 52.8775 ;
      END
   END dout0[15]
   PIN dout0[16]
      DIRECTION OUTPUT ;
      PORT
         LAYER metal3 ;
         RECT  88.235 52.7425 88.37 52.8775 ;
      END
   END dout0[16]
   PIN dout0[17]
      DIRECTION OUTPUT ;
      PORT
         LAYER metal3 ;
         RECT  88.94 52.7425 89.075 52.8775 ;
      END
   END dout0[17]
   PIN dout0[18]
      DIRECTION OUTPUT ;
      PORT
         LAYER metal3 ;
         RECT  89.645 52.7425 89.78 52.8775 ;
      END
   END dout0[18]
   PIN dout0[19]
      DIRECTION OUTPUT ;
      PORT
         LAYER metal3 ;
         RECT  90.35 52.7425 90.485 52.8775 ;
      END
   END dout0[19]
   PIN dout0[20]
      DIRECTION OUTPUT ;
      PORT
         LAYER metal3 ;
         RECT  91.055 52.7425 91.19 52.8775 ;
      END
   END dout0[20]
   PIN dout0[21]
      DIRECTION OUTPUT ;
      PORT
         LAYER metal3 ;
         RECT  91.76 52.7425 91.895 52.8775 ;
      END
   END dout0[21]
   PIN dout0[22]
      DIRECTION OUTPUT ;
      PORT
         LAYER metal3 ;
         RECT  92.465 52.7425 92.6 52.8775 ;
      END
   END dout0[22]
   PIN dout0[23]
      DIRECTION OUTPUT ;
      PORT
         LAYER metal3 ;
         RECT  93.17 52.7425 93.305 52.8775 ;
      END
   END dout0[23]
   PIN dout0[24]
      DIRECTION OUTPUT ;
      PORT
         LAYER metal3 ;
         RECT  93.875 52.7425 94.01 52.8775 ;
      END
   END dout0[24]
   PIN dout0[25]
      DIRECTION OUTPUT ;
      PORT
         LAYER metal3 ;
         RECT  94.58 52.7425 94.715 52.8775 ;
      END
   END dout0[25]
   PIN dout0[26]
      DIRECTION OUTPUT ;
      PORT
         LAYER metal3 ;
         RECT  95.285 52.7425 95.42 52.8775 ;
      END
   END dout0[26]
   PIN dout0[27]
      DIRECTION OUTPUT ;
      PORT
         LAYER metal3 ;
         RECT  95.99 52.7425 96.125 52.8775 ;
      END
   END dout0[27]
   PIN dout0[28]
      DIRECTION OUTPUT ;
      PORT
         LAYER metal3 ;
         RECT  96.695 52.7425 96.83 52.8775 ;
      END
   END dout0[28]
   PIN dout0[29]
      DIRECTION OUTPUT ;
      PORT
         LAYER metal3 ;
         RECT  97.4 52.7425 97.535 52.8775 ;
      END
   END dout0[29]
   PIN dout0[30]
      DIRECTION OUTPUT ;
      PORT
         LAYER metal3 ;
         RECT  98.105 52.7425 98.24 52.8775 ;
      END
   END dout0[30]
   PIN dout0[31]
      DIRECTION OUTPUT ;
      PORT
         LAYER metal3 ;
         RECT  98.81 52.7425 98.945 52.8775 ;
      END
   END dout0[31]
   PIN dout0[32]
      DIRECTION OUTPUT ;
      PORT
         LAYER metal3 ;
         RECT  99.515 52.7425 99.65 52.8775 ;
      END
   END dout0[32]
   PIN dout0[33]
      DIRECTION OUTPUT ;
      PORT
         LAYER metal3 ;
         RECT  100.22 52.7425 100.355 52.8775 ;
      END
   END dout0[33]
   PIN dout0[34]
      DIRECTION OUTPUT ;
      PORT
         LAYER metal3 ;
         RECT  100.925 52.7425 101.06 52.8775 ;
      END
   END dout0[34]
   PIN dout0[35]
      DIRECTION OUTPUT ;
      PORT
         LAYER metal3 ;
         RECT  101.63 52.7425 101.765 52.8775 ;
      END
   END dout0[35]
   PIN dout0[36]
      DIRECTION OUTPUT ;
      PORT
         LAYER metal3 ;
         RECT  102.335 52.7425 102.47 52.8775 ;
      END
   END dout0[36]
   PIN dout0[37]
      DIRECTION OUTPUT ;
      PORT
         LAYER metal3 ;
         RECT  103.04 52.7425 103.175 52.8775 ;
      END
   END dout0[37]
   PIN dout0[38]
      DIRECTION OUTPUT ;
      PORT
         LAYER metal3 ;
         RECT  103.745 52.7425 103.88 52.8775 ;
      END
   END dout0[38]
   PIN dout0[39]
      DIRECTION OUTPUT ;
      PORT
         LAYER metal3 ;
         RECT  104.45 52.7425 104.585 52.8775 ;
      END
   END dout0[39]
   PIN dout0[40]
      DIRECTION OUTPUT ;
      PORT
         LAYER metal3 ;
         RECT  105.155 52.7425 105.29 52.8775 ;
      END
   END dout0[40]
   PIN dout0[41]
      DIRECTION OUTPUT ;
      PORT
         LAYER metal3 ;
         RECT  105.86 52.7425 105.995 52.8775 ;
      END
   END dout0[41]
   PIN dout0[42]
      DIRECTION OUTPUT ;
      PORT
         LAYER metal3 ;
         RECT  106.565 52.7425 106.7 52.8775 ;
      END
   END dout0[42]
   PIN dout0[43]
      DIRECTION OUTPUT ;
      PORT
         LAYER metal3 ;
         RECT  107.27 52.7425 107.405 52.8775 ;
      END
   END dout0[43]
   PIN dout0[44]
      DIRECTION OUTPUT ;
      PORT
         LAYER metal3 ;
         RECT  107.975 52.7425 108.11 52.8775 ;
      END
   END dout0[44]
   PIN dout0[45]
      DIRECTION OUTPUT ;
      PORT
         LAYER metal3 ;
         RECT  108.68 52.7425 108.815 52.8775 ;
      END
   END dout0[45]
   PIN dout0[46]
      DIRECTION OUTPUT ;
      PORT
         LAYER metal3 ;
         RECT  109.385 52.7425 109.52 52.8775 ;
      END
   END dout0[46]
   PIN dout0[47]
      DIRECTION OUTPUT ;
      PORT
         LAYER metal3 ;
         RECT  110.09 52.7425 110.225 52.8775 ;
      END
   END dout0[47]
   PIN dout0[48]
      DIRECTION OUTPUT ;
      PORT
         LAYER metal3 ;
         RECT  110.795 52.7425 110.93 52.8775 ;
      END
   END dout0[48]
   PIN dout0[49]
      DIRECTION OUTPUT ;
      PORT
         LAYER metal3 ;
         RECT  111.5 52.7425 111.635 52.8775 ;
      END
   END dout0[49]
   PIN dout0[50]
      DIRECTION OUTPUT ;
      PORT
         LAYER metal3 ;
         RECT  112.205 52.7425 112.34 52.8775 ;
      END
   END dout0[50]
   PIN dout0[51]
      DIRECTION OUTPUT ;
      PORT
         LAYER metal3 ;
         RECT  112.91 52.7425 113.045 52.8775 ;
      END
   END dout0[51]
   PIN dout0[52]
      DIRECTION OUTPUT ;
      PORT
         LAYER metal3 ;
         RECT  113.615 52.7425 113.75 52.8775 ;
      END
   END dout0[52]
   PIN dout0[53]
      DIRECTION OUTPUT ;
      PORT
         LAYER metal3 ;
         RECT  114.32 52.7425 114.455 52.8775 ;
      END
   END dout0[53]
   PIN dout0[54]
      DIRECTION OUTPUT ;
      PORT
         LAYER metal3 ;
         RECT  115.025 52.7425 115.16 52.8775 ;
      END
   END dout0[54]
   PIN dout0[55]
      DIRECTION OUTPUT ;
      PORT
         LAYER metal3 ;
         RECT  115.73 52.7425 115.865 52.8775 ;
      END
   END dout0[55]
   PIN dout0[56]
      DIRECTION OUTPUT ;
      PORT
         LAYER metal3 ;
         RECT  116.435 52.7425 116.57 52.8775 ;
      END
   END dout0[56]
   PIN dout0[57]
      DIRECTION OUTPUT ;
      PORT
         LAYER metal3 ;
         RECT  117.14 52.7425 117.275 52.8775 ;
      END
   END dout0[57]
   PIN dout0[58]
      DIRECTION OUTPUT ;
      PORT
         LAYER metal3 ;
         RECT  117.845 52.7425 117.98 52.8775 ;
      END
   END dout0[58]
   PIN dout0[59]
      DIRECTION OUTPUT ;
      PORT
         LAYER metal3 ;
         RECT  118.55 52.7425 118.685 52.8775 ;
      END
   END dout0[59]
   PIN dout0[60]
      DIRECTION OUTPUT ;
      PORT
         LAYER metal3 ;
         RECT  119.255 52.7425 119.39 52.8775 ;
      END
   END dout0[60]
   PIN dout0[61]
      DIRECTION OUTPUT ;
      PORT
         LAYER metal3 ;
         RECT  119.96 52.7425 120.095 52.8775 ;
      END
   END dout0[61]
   PIN dout0[62]
      DIRECTION OUTPUT ;
      PORT
         LAYER metal3 ;
         RECT  120.665 52.7425 120.8 52.8775 ;
      END
   END dout0[62]
   PIN dout0[63]
      DIRECTION OUTPUT ;
      PORT
         LAYER metal3 ;
         RECT  121.37 52.7425 121.505 52.8775 ;
      END
   END dout0[63]
   PIN dout0[64]
      DIRECTION OUTPUT ;
      PORT
         LAYER metal3 ;
         RECT  122.075 52.7425 122.21 52.8775 ;
      END
   END dout0[64]
   PIN dout0[65]
      DIRECTION OUTPUT ;
      PORT
         LAYER metal3 ;
         RECT  122.78 52.7425 122.915 52.8775 ;
      END
   END dout0[65]
   PIN dout0[66]
      DIRECTION OUTPUT ;
      PORT
         LAYER metal3 ;
         RECT  123.485 52.7425 123.62 52.8775 ;
      END
   END dout0[66]
   PIN dout0[67]
      DIRECTION OUTPUT ;
      PORT
         LAYER metal3 ;
         RECT  124.19 52.7425 124.325 52.8775 ;
      END
   END dout0[67]
   PIN dout0[68]
      DIRECTION OUTPUT ;
      PORT
         LAYER metal3 ;
         RECT  124.895 52.7425 125.03 52.8775 ;
      END
   END dout0[68]
   PIN dout0[69]
      DIRECTION OUTPUT ;
      PORT
         LAYER metal3 ;
         RECT  125.6 52.7425 125.735 52.8775 ;
      END
   END dout0[69]
   PIN dout0[70]
      DIRECTION OUTPUT ;
      PORT
         LAYER metal3 ;
         RECT  126.305 52.7425 126.44 52.8775 ;
      END
   END dout0[70]
   PIN dout0[71]
      DIRECTION OUTPUT ;
      PORT
         LAYER metal3 ;
         RECT  127.01 52.7425 127.145 52.8775 ;
      END
   END dout0[71]
   PIN dout0[72]
      DIRECTION OUTPUT ;
      PORT
         LAYER metal3 ;
         RECT  127.715 52.7425 127.85 52.8775 ;
      END
   END dout0[72]
   PIN dout0[73]
      DIRECTION OUTPUT ;
      PORT
         LAYER metal3 ;
         RECT  128.42 52.7425 128.555 52.8775 ;
      END
   END dout0[73]
   PIN dout0[74]
      DIRECTION OUTPUT ;
      PORT
         LAYER metal3 ;
         RECT  129.125 52.7425 129.26 52.8775 ;
      END
   END dout0[74]
   PIN dout0[75]
      DIRECTION OUTPUT ;
      PORT
         LAYER metal3 ;
         RECT  129.83 52.7425 129.965 52.8775 ;
      END
   END dout0[75]
   PIN dout0[76]
      DIRECTION OUTPUT ;
      PORT
         LAYER metal3 ;
         RECT  130.535 52.7425 130.67 52.8775 ;
      END
   END dout0[76]
   PIN dout0[77]
      DIRECTION OUTPUT ;
      PORT
         LAYER metal3 ;
         RECT  131.24 52.7425 131.375 52.8775 ;
      END
   END dout0[77]
   PIN dout0[78]
      DIRECTION OUTPUT ;
      PORT
         LAYER metal3 ;
         RECT  131.945 52.7425 132.08 52.8775 ;
      END
   END dout0[78]
   PIN dout0[79]
      DIRECTION OUTPUT ;
      PORT
         LAYER metal3 ;
         RECT  132.65 52.7425 132.785 52.8775 ;
      END
   END dout0[79]
   PIN dout0[80]
      DIRECTION OUTPUT ;
      PORT
         LAYER metal3 ;
         RECT  133.355 52.7425 133.49 52.8775 ;
      END
   END dout0[80]
   PIN dout0[81]
      DIRECTION OUTPUT ;
      PORT
         LAYER metal3 ;
         RECT  134.06 52.7425 134.195 52.8775 ;
      END
   END dout0[81]
   PIN dout0[82]
      DIRECTION OUTPUT ;
      PORT
         LAYER metal3 ;
         RECT  134.765 52.7425 134.9 52.8775 ;
      END
   END dout0[82]
   PIN dout0[83]
      DIRECTION OUTPUT ;
      PORT
         LAYER metal3 ;
         RECT  135.47 52.7425 135.605 52.8775 ;
      END
   END dout0[83]
   PIN dout0[84]
      DIRECTION OUTPUT ;
      PORT
         LAYER metal3 ;
         RECT  136.175 52.7425 136.31 52.8775 ;
      END
   END dout0[84]
   PIN dout0[85]
      DIRECTION OUTPUT ;
      PORT
         LAYER metal3 ;
         RECT  136.88 52.7425 137.015 52.8775 ;
      END
   END dout0[85]
   PIN dout0[86]
      DIRECTION OUTPUT ;
      PORT
         LAYER metal3 ;
         RECT  137.585 52.7425 137.72 52.8775 ;
      END
   END dout0[86]
   PIN dout0[87]
      DIRECTION OUTPUT ;
      PORT
         LAYER metal3 ;
         RECT  138.29 52.7425 138.425 52.8775 ;
      END
   END dout0[87]
   PIN dout0[88]
      DIRECTION OUTPUT ;
      PORT
         LAYER metal3 ;
         RECT  138.995 52.7425 139.13 52.8775 ;
      END
   END dout0[88]
   PIN dout0[89]
      DIRECTION OUTPUT ;
      PORT
         LAYER metal3 ;
         RECT  139.7 52.7425 139.835 52.8775 ;
      END
   END dout0[89]
   PIN dout0[90]
      DIRECTION OUTPUT ;
      PORT
         LAYER metal3 ;
         RECT  140.405 52.7425 140.54 52.8775 ;
      END
   END dout0[90]
   PIN dout0[91]
      DIRECTION OUTPUT ;
      PORT
         LAYER metal3 ;
         RECT  141.11 52.7425 141.245 52.8775 ;
      END
   END dout0[91]
   PIN dout0[92]
      DIRECTION OUTPUT ;
      PORT
         LAYER metal3 ;
         RECT  141.815 52.7425 141.95 52.8775 ;
      END
   END dout0[92]
   PIN dout0[93]
      DIRECTION OUTPUT ;
      PORT
         LAYER metal3 ;
         RECT  142.52 52.7425 142.655 52.8775 ;
      END
   END dout0[93]
   PIN dout0[94]
      DIRECTION OUTPUT ;
      PORT
         LAYER metal3 ;
         RECT  143.225 52.7425 143.36 52.8775 ;
      END
   END dout0[94]
   PIN dout0[95]
      DIRECTION OUTPUT ;
      PORT
         LAYER metal3 ;
         RECT  143.93 52.7425 144.065 52.8775 ;
      END
   END dout0[95]
   PIN dout0[96]
      DIRECTION OUTPUT ;
      PORT
         LAYER metal3 ;
         RECT  144.635 52.7425 144.77 52.8775 ;
      END
   END dout0[96]
   PIN dout0[97]
      DIRECTION OUTPUT ;
      PORT
         LAYER metal3 ;
         RECT  145.34 52.7425 145.475 52.8775 ;
      END
   END dout0[97]
   PIN dout0[98]
      DIRECTION OUTPUT ;
      PORT
         LAYER metal3 ;
         RECT  146.045 52.7425 146.18 52.8775 ;
      END
   END dout0[98]
   PIN dout0[99]
      DIRECTION OUTPUT ;
      PORT
         LAYER metal3 ;
         RECT  146.75 52.7425 146.885 52.8775 ;
      END
   END dout0[99]
   PIN dout0[100]
      DIRECTION OUTPUT ;
      PORT
         LAYER metal3 ;
         RECT  147.455 52.7425 147.59 52.8775 ;
      END
   END dout0[100]
   PIN dout0[101]
      DIRECTION OUTPUT ;
      PORT
         LAYER metal3 ;
         RECT  148.16 52.7425 148.295 52.8775 ;
      END
   END dout0[101]
   PIN dout0[102]
      DIRECTION OUTPUT ;
      PORT
         LAYER metal3 ;
         RECT  148.865 52.7425 149.0 52.8775 ;
      END
   END dout0[102]
   PIN dout0[103]
      DIRECTION OUTPUT ;
      PORT
         LAYER metal3 ;
         RECT  149.57 52.7425 149.705 52.8775 ;
      END
   END dout0[103]
   PIN dout0[104]
      DIRECTION OUTPUT ;
      PORT
         LAYER metal3 ;
         RECT  150.275 52.7425 150.41 52.8775 ;
      END
   END dout0[104]
   PIN dout0[105]
      DIRECTION OUTPUT ;
      PORT
         LAYER metal3 ;
         RECT  150.98 52.7425 151.115 52.8775 ;
      END
   END dout0[105]
   PIN dout0[106]
      DIRECTION OUTPUT ;
      PORT
         LAYER metal3 ;
         RECT  151.685 52.7425 151.82 52.8775 ;
      END
   END dout0[106]
   PIN dout0[107]
      DIRECTION OUTPUT ;
      PORT
         LAYER metal3 ;
         RECT  152.39 52.7425 152.525 52.8775 ;
      END
   END dout0[107]
   PIN dout0[108]
      DIRECTION OUTPUT ;
      PORT
         LAYER metal3 ;
         RECT  153.095 52.7425 153.23 52.8775 ;
      END
   END dout0[108]
   PIN dout0[109]
      DIRECTION OUTPUT ;
      PORT
         LAYER metal3 ;
         RECT  153.8 52.7425 153.935 52.8775 ;
      END
   END dout0[109]
   PIN dout0[110]
      DIRECTION OUTPUT ;
      PORT
         LAYER metal3 ;
         RECT  154.505 52.7425 154.64 52.8775 ;
      END
   END dout0[110]
   PIN dout0[111]
      DIRECTION OUTPUT ;
      PORT
         LAYER metal3 ;
         RECT  155.21 52.7425 155.345 52.8775 ;
      END
   END dout0[111]
   PIN dout0[112]
      DIRECTION OUTPUT ;
      PORT
         LAYER metal3 ;
         RECT  155.915 52.7425 156.05 52.8775 ;
      END
   END dout0[112]
   PIN dout0[113]
      DIRECTION OUTPUT ;
      PORT
         LAYER metal3 ;
         RECT  156.62 52.7425 156.755 52.8775 ;
      END
   END dout0[113]
   PIN dout0[114]
      DIRECTION OUTPUT ;
      PORT
         LAYER metal3 ;
         RECT  157.325 52.7425 157.46 52.8775 ;
      END
   END dout0[114]
   PIN dout0[115]
      DIRECTION OUTPUT ;
      PORT
         LAYER metal3 ;
         RECT  158.03 52.7425 158.165 52.8775 ;
      END
   END dout0[115]
   PIN dout0[116]
      DIRECTION OUTPUT ;
      PORT
         LAYER metal3 ;
         RECT  158.735 52.7425 158.87 52.8775 ;
      END
   END dout0[116]
   PIN dout0[117]
      DIRECTION OUTPUT ;
      PORT
         LAYER metal3 ;
         RECT  159.44 52.7425 159.575 52.8775 ;
      END
   END dout0[117]
   PIN dout0[118]
      DIRECTION OUTPUT ;
      PORT
         LAYER metal3 ;
         RECT  160.145 52.7425 160.28 52.8775 ;
      END
   END dout0[118]
   PIN dout0[119]
      DIRECTION OUTPUT ;
      PORT
         LAYER metal3 ;
         RECT  160.85 52.7425 160.985 52.8775 ;
      END
   END dout0[119]
   PIN dout0[120]
      DIRECTION OUTPUT ;
      PORT
         LAYER metal3 ;
         RECT  161.555 52.7425 161.69 52.8775 ;
      END
   END dout0[120]
   PIN dout0[121]
      DIRECTION OUTPUT ;
      PORT
         LAYER metal3 ;
         RECT  162.26 52.7425 162.395 52.8775 ;
      END
   END dout0[121]
   PIN dout0[122]
      DIRECTION OUTPUT ;
      PORT
         LAYER metal3 ;
         RECT  162.965 52.7425 163.1 52.8775 ;
      END
   END dout0[122]
   PIN dout0[123]
      DIRECTION OUTPUT ;
      PORT
         LAYER metal3 ;
         RECT  163.67 52.7425 163.805 52.8775 ;
      END
   END dout0[123]
   PIN dout0[124]
      DIRECTION OUTPUT ;
      PORT
         LAYER metal3 ;
         RECT  164.375 52.7425 164.51 52.8775 ;
      END
   END dout0[124]
   PIN dout0[125]
      DIRECTION OUTPUT ;
      PORT
         LAYER metal3 ;
         RECT  165.08 52.7425 165.215 52.8775 ;
      END
   END dout0[125]
   PIN dout0[126]
      DIRECTION OUTPUT ;
      PORT
         LAYER metal3 ;
         RECT  165.785 52.7425 165.92 52.8775 ;
      END
   END dout0[126]
   PIN dout0[127]
      DIRECTION OUTPUT ;
      PORT
         LAYER metal3 ;
         RECT  166.49 52.7425 166.625 52.8775 ;
      END
   END dout0[127]
   PIN dout0[128]
      DIRECTION OUTPUT ;
      PORT
         LAYER metal3 ;
         RECT  167.195 52.7425 167.33 52.8775 ;
      END
   END dout0[128]
   PIN dout0[129]
      DIRECTION OUTPUT ;
      PORT
         LAYER metal3 ;
         RECT  167.9 52.7425 168.035 52.8775 ;
      END
   END dout0[129]
   PIN dout0[130]
      DIRECTION OUTPUT ;
      PORT
         LAYER metal3 ;
         RECT  168.605 52.7425 168.74 52.8775 ;
      END
   END dout0[130]
   PIN dout0[131]
      DIRECTION OUTPUT ;
      PORT
         LAYER metal3 ;
         RECT  169.31 52.7425 169.445 52.8775 ;
      END
   END dout0[131]
   PIN dout0[132]
      DIRECTION OUTPUT ;
      PORT
         LAYER metal3 ;
         RECT  170.015 52.7425 170.15 52.8775 ;
      END
   END dout0[132]
   PIN dout0[133]
      DIRECTION OUTPUT ;
      PORT
         LAYER metal3 ;
         RECT  170.72 52.7425 170.855 52.8775 ;
      END
   END dout0[133]
   PIN dout0[134]
      DIRECTION OUTPUT ;
      PORT
         LAYER metal3 ;
         RECT  171.425 52.7425 171.56 52.8775 ;
      END
   END dout0[134]
   PIN dout0[135]
      DIRECTION OUTPUT ;
      PORT
         LAYER metal3 ;
         RECT  172.13 52.7425 172.265 52.8775 ;
      END
   END dout0[135]
   PIN dout0[136]
      DIRECTION OUTPUT ;
      PORT
         LAYER metal3 ;
         RECT  172.835 52.7425 172.97 52.8775 ;
      END
   END dout0[136]
   PIN dout0[137]
      DIRECTION OUTPUT ;
      PORT
         LAYER metal3 ;
         RECT  173.54 52.7425 173.675 52.8775 ;
      END
   END dout0[137]
   PIN dout0[138]
      DIRECTION OUTPUT ;
      PORT
         LAYER metal3 ;
         RECT  174.245 52.7425 174.38 52.8775 ;
      END
   END dout0[138]
   PIN dout0[139]
      DIRECTION OUTPUT ;
      PORT
         LAYER metal3 ;
         RECT  174.95 52.7425 175.085 52.8775 ;
      END
   END dout0[139]
   PIN dout0[140]
      DIRECTION OUTPUT ;
      PORT
         LAYER metal3 ;
         RECT  175.655 52.7425 175.79 52.8775 ;
      END
   END dout0[140]
   PIN dout0[141]
      DIRECTION OUTPUT ;
      PORT
         LAYER metal3 ;
         RECT  176.36 52.7425 176.495 52.8775 ;
      END
   END dout0[141]
   PIN dout0[142]
      DIRECTION OUTPUT ;
      PORT
         LAYER metal3 ;
         RECT  177.065 52.7425 177.2 52.8775 ;
      END
   END dout0[142]
   PIN dout0[143]
      DIRECTION OUTPUT ;
      PORT
         LAYER metal3 ;
         RECT  177.77 52.7425 177.905 52.8775 ;
      END
   END dout0[143]
   PIN dout0[144]
      DIRECTION OUTPUT ;
      PORT
         LAYER metal3 ;
         RECT  178.475 52.7425 178.61 52.8775 ;
      END
   END dout0[144]
   PIN dout0[145]
      DIRECTION OUTPUT ;
      PORT
         LAYER metal3 ;
         RECT  179.18 52.7425 179.315 52.8775 ;
      END
   END dout0[145]
   PIN dout0[146]
      DIRECTION OUTPUT ;
      PORT
         LAYER metal3 ;
         RECT  179.885 52.7425 180.02 52.8775 ;
      END
   END dout0[146]
   PIN dout0[147]
      DIRECTION OUTPUT ;
      PORT
         LAYER metal3 ;
         RECT  180.59 52.7425 180.725 52.8775 ;
      END
   END dout0[147]
   PIN dout0[148]
      DIRECTION OUTPUT ;
      PORT
         LAYER metal3 ;
         RECT  181.295 52.7425 181.43 52.8775 ;
      END
   END dout0[148]
   PIN dout0[149]
      DIRECTION OUTPUT ;
      PORT
         LAYER metal3 ;
         RECT  182.0 52.7425 182.135 52.8775 ;
      END
   END dout0[149]
   PIN dout0[150]
      DIRECTION OUTPUT ;
      PORT
         LAYER metal3 ;
         RECT  182.705 52.7425 182.84 52.8775 ;
      END
   END dout0[150]
   PIN dout0[151]
      DIRECTION OUTPUT ;
      PORT
         LAYER metal3 ;
         RECT  183.41 52.7425 183.545 52.8775 ;
      END
   END dout0[151]
   PIN dout0[152]
      DIRECTION OUTPUT ;
      PORT
         LAYER metal3 ;
         RECT  184.115 52.7425 184.25 52.8775 ;
      END
   END dout0[152]
   PIN dout0[153]
      DIRECTION OUTPUT ;
      PORT
         LAYER metal3 ;
         RECT  184.82 52.7425 184.955 52.8775 ;
      END
   END dout0[153]
   PIN dout0[154]
      DIRECTION OUTPUT ;
      PORT
         LAYER metal3 ;
         RECT  185.525 52.7425 185.66 52.8775 ;
      END
   END dout0[154]
   PIN dout0[155]
      DIRECTION OUTPUT ;
      PORT
         LAYER metal3 ;
         RECT  186.23 52.7425 186.365 52.8775 ;
      END
   END dout0[155]
   PIN dout0[156]
      DIRECTION OUTPUT ;
      PORT
         LAYER metal3 ;
         RECT  186.935 52.7425 187.07 52.8775 ;
      END
   END dout0[156]
   PIN dout0[157]
      DIRECTION OUTPUT ;
      PORT
         LAYER metal3 ;
         RECT  187.64 52.7425 187.775 52.8775 ;
      END
   END dout0[157]
   PIN dout0[158]
      DIRECTION OUTPUT ;
      PORT
         LAYER metal3 ;
         RECT  188.345 52.7425 188.48 52.8775 ;
      END
   END dout0[158]
   PIN dout0[159]
      DIRECTION OUTPUT ;
      PORT
         LAYER metal3 ;
         RECT  189.05 52.7425 189.185 52.8775 ;
      END
   END dout0[159]
   PIN dout0[160]
      DIRECTION OUTPUT ;
      PORT
         LAYER metal3 ;
         RECT  189.755 52.7425 189.89 52.8775 ;
      END
   END dout0[160]
   PIN dout0[161]
      DIRECTION OUTPUT ;
      PORT
         LAYER metal3 ;
         RECT  190.46 52.7425 190.595 52.8775 ;
      END
   END dout0[161]
   PIN dout0[162]
      DIRECTION OUTPUT ;
      PORT
         LAYER metal3 ;
         RECT  191.165 52.7425 191.3 52.8775 ;
      END
   END dout0[162]
   PIN dout0[163]
      DIRECTION OUTPUT ;
      PORT
         LAYER metal3 ;
         RECT  191.87 52.7425 192.005 52.8775 ;
      END
   END dout0[163]
   PIN dout0[164]
      DIRECTION OUTPUT ;
      PORT
         LAYER metal3 ;
         RECT  192.575 52.7425 192.71 52.8775 ;
      END
   END dout0[164]
   PIN dout0[165]
      DIRECTION OUTPUT ;
      PORT
         LAYER metal3 ;
         RECT  193.28 52.7425 193.415 52.8775 ;
      END
   END dout0[165]
   PIN dout0[166]
      DIRECTION OUTPUT ;
      PORT
         LAYER metal3 ;
         RECT  193.985 52.7425 194.12 52.8775 ;
      END
   END dout0[166]
   PIN dout0[167]
      DIRECTION OUTPUT ;
      PORT
         LAYER metal3 ;
         RECT  194.69 52.7425 194.825 52.8775 ;
      END
   END dout0[167]
   PIN dout0[168]
      DIRECTION OUTPUT ;
      PORT
         LAYER metal3 ;
         RECT  195.395 52.7425 195.53 52.8775 ;
      END
   END dout0[168]
   PIN dout0[169]
      DIRECTION OUTPUT ;
      PORT
         LAYER metal3 ;
         RECT  196.1 52.7425 196.235 52.8775 ;
      END
   END dout0[169]
   PIN dout0[170]
      DIRECTION OUTPUT ;
      PORT
         LAYER metal3 ;
         RECT  196.805 52.7425 196.94 52.8775 ;
      END
   END dout0[170]
   PIN dout0[171]
      DIRECTION OUTPUT ;
      PORT
         LAYER metal3 ;
         RECT  197.51 52.7425 197.645 52.8775 ;
      END
   END dout0[171]
   PIN dout0[172]
      DIRECTION OUTPUT ;
      PORT
         LAYER metal3 ;
         RECT  198.215 52.7425 198.35 52.8775 ;
      END
   END dout0[172]
   PIN dout0[173]
      DIRECTION OUTPUT ;
      PORT
         LAYER metal3 ;
         RECT  198.92 52.7425 199.055 52.8775 ;
      END
   END dout0[173]
   PIN dout0[174]
      DIRECTION OUTPUT ;
      PORT
         LAYER metal3 ;
         RECT  199.625 52.7425 199.76 52.8775 ;
      END
   END dout0[174]
   PIN dout0[175]
      DIRECTION OUTPUT ;
      PORT
         LAYER metal3 ;
         RECT  200.33 52.7425 200.465 52.8775 ;
      END
   END dout0[175]
   PIN dout0[176]
      DIRECTION OUTPUT ;
      PORT
         LAYER metal3 ;
         RECT  201.035 52.7425 201.17 52.8775 ;
      END
   END dout0[176]
   PIN dout0[177]
      DIRECTION OUTPUT ;
      PORT
         LAYER metal3 ;
         RECT  201.74 52.7425 201.875 52.8775 ;
      END
   END dout0[177]
   PIN dout0[178]
      DIRECTION OUTPUT ;
      PORT
         LAYER metal3 ;
         RECT  202.445 52.7425 202.58 52.8775 ;
      END
   END dout0[178]
   PIN dout0[179]
      DIRECTION OUTPUT ;
      PORT
         LAYER metal3 ;
         RECT  203.15 52.7425 203.285 52.8775 ;
      END
   END dout0[179]
   PIN dout0[180]
      DIRECTION OUTPUT ;
      PORT
         LAYER metal3 ;
         RECT  203.855 52.7425 203.99 52.8775 ;
      END
   END dout0[180]
   PIN dout0[181]
      DIRECTION OUTPUT ;
      PORT
         LAYER metal3 ;
         RECT  204.56 52.7425 204.695 52.8775 ;
      END
   END dout0[181]
   PIN dout0[182]
      DIRECTION OUTPUT ;
      PORT
         LAYER metal3 ;
         RECT  205.265 52.7425 205.4 52.8775 ;
      END
   END dout0[182]
   PIN dout0[183]
      DIRECTION OUTPUT ;
      PORT
         LAYER metal3 ;
         RECT  205.97 52.7425 206.105 52.8775 ;
      END
   END dout0[183]
   PIN dout0[184]
      DIRECTION OUTPUT ;
      PORT
         LAYER metal3 ;
         RECT  206.675 52.7425 206.81 52.8775 ;
      END
   END dout0[184]
   PIN dout0[185]
      DIRECTION OUTPUT ;
      PORT
         LAYER metal3 ;
         RECT  207.38 52.7425 207.515 52.8775 ;
      END
   END dout0[185]
   PIN dout0[186]
      DIRECTION OUTPUT ;
      PORT
         LAYER metal3 ;
         RECT  208.085 52.7425 208.22 52.8775 ;
      END
   END dout0[186]
   PIN dout0[187]
      DIRECTION OUTPUT ;
      PORT
         LAYER metal3 ;
         RECT  208.79 52.7425 208.925 52.8775 ;
      END
   END dout0[187]
   PIN dout0[188]
      DIRECTION OUTPUT ;
      PORT
         LAYER metal3 ;
         RECT  209.495 52.7425 209.63 52.8775 ;
      END
   END dout0[188]
   PIN dout0[189]
      DIRECTION OUTPUT ;
      PORT
         LAYER metal3 ;
         RECT  210.2 52.7425 210.335 52.8775 ;
      END
   END dout0[189]
   PIN dout0[190]
      DIRECTION OUTPUT ;
      PORT
         LAYER metal3 ;
         RECT  210.905 52.7425 211.04 52.8775 ;
      END
   END dout0[190]
   PIN dout0[191]
      DIRECTION OUTPUT ;
      PORT
         LAYER metal3 ;
         RECT  211.61 52.7425 211.745 52.8775 ;
      END
   END dout0[191]
   PIN vdd
      DIRECTION INOUT ;
      USE POWER ; 
      SHAPE ABUTMENT ; 
      PORT
      END
   END vdd
   PIN gnd
      DIRECTION INOUT ;
      USE GROUND ; 
      SHAPE ABUTMENT ; 
      PORT
      END
   END gnd
   OBS
   LAYER  metal1 ;
      RECT  0.14 0.14 639.23 152.225 ;
   LAYER  metal2 ;
      RECT  0.14 0.14 639.23 152.225 ;
   LAYER  metal3 ;
      RECT  0.14 0.14 90.325 0.8975 ;
      RECT  90.325 0.14 90.74 0.8975 ;
      RECT  90.74 0.14 639.23 0.8975 ;
      RECT  90.74 0.8975 93.185 1.3125 ;
      RECT  93.6 0.8975 96.045 1.3125 ;
      RECT  96.46 0.8975 98.905 1.3125 ;
      RECT  99.32 0.8975 101.765 1.3125 ;
      RECT  102.18 0.8975 104.625 1.3125 ;
      RECT  105.04 0.8975 107.485 1.3125 ;
      RECT  107.9 0.8975 110.345 1.3125 ;
      RECT  110.76 0.8975 113.205 1.3125 ;
      RECT  113.62 0.8975 116.065 1.3125 ;
      RECT  116.48 0.8975 118.925 1.3125 ;
      RECT  119.34 0.8975 121.785 1.3125 ;
      RECT  122.2 0.8975 124.645 1.3125 ;
      RECT  125.06 0.8975 127.505 1.3125 ;
      RECT  127.92 0.8975 130.365 1.3125 ;
      RECT  130.78 0.8975 133.225 1.3125 ;
      RECT  133.64 0.8975 136.085 1.3125 ;
      RECT  136.5 0.8975 138.945 1.3125 ;
      RECT  139.36 0.8975 141.805 1.3125 ;
      RECT  142.22 0.8975 144.665 1.3125 ;
      RECT  145.08 0.8975 147.525 1.3125 ;
      RECT  147.94 0.8975 150.385 1.3125 ;
      RECT  150.8 0.8975 153.245 1.3125 ;
      RECT  153.66 0.8975 156.105 1.3125 ;
      RECT  156.52 0.8975 158.965 1.3125 ;
      RECT  159.38 0.8975 161.825 1.3125 ;
      RECT  162.24 0.8975 164.685 1.3125 ;
      RECT  165.1 0.8975 167.545 1.3125 ;
      RECT  167.96 0.8975 170.405 1.3125 ;
      RECT  170.82 0.8975 173.265 1.3125 ;
      RECT  173.68 0.8975 176.125 1.3125 ;
      RECT  176.54 0.8975 178.985 1.3125 ;
      RECT  179.4 0.8975 181.845 1.3125 ;
      RECT  182.26 0.8975 184.705 1.3125 ;
      RECT  185.12 0.8975 187.565 1.3125 ;
      RECT  187.98 0.8975 190.425 1.3125 ;
      RECT  190.84 0.8975 193.285 1.3125 ;
      RECT  193.7 0.8975 196.145 1.3125 ;
      RECT  196.56 0.8975 199.005 1.3125 ;
      RECT  199.42 0.8975 201.865 1.3125 ;
      RECT  202.28 0.8975 204.725 1.3125 ;
      RECT  205.14 0.8975 207.585 1.3125 ;
      RECT  208.0 0.8975 210.445 1.3125 ;
      RECT  210.86 0.8975 213.305 1.3125 ;
      RECT  213.72 0.8975 216.165 1.3125 ;
      RECT  216.58 0.8975 219.025 1.3125 ;
      RECT  219.44 0.8975 221.885 1.3125 ;
      RECT  222.3 0.8975 224.745 1.3125 ;
      RECT  225.16 0.8975 227.605 1.3125 ;
      RECT  228.02 0.8975 230.465 1.3125 ;
      RECT  230.88 0.8975 233.325 1.3125 ;
      RECT  233.74 0.8975 236.185 1.3125 ;
      RECT  236.6 0.8975 239.045 1.3125 ;
      RECT  239.46 0.8975 241.905 1.3125 ;
      RECT  242.32 0.8975 244.765 1.3125 ;
      RECT  245.18 0.8975 247.625 1.3125 ;
      RECT  248.04 0.8975 250.485 1.3125 ;
      RECT  250.9 0.8975 253.345 1.3125 ;
      RECT  253.76 0.8975 256.205 1.3125 ;
      RECT  256.62 0.8975 259.065 1.3125 ;
      RECT  259.48 0.8975 261.925 1.3125 ;
      RECT  262.34 0.8975 264.785 1.3125 ;
      RECT  265.2 0.8975 267.645 1.3125 ;
      RECT  268.06 0.8975 270.505 1.3125 ;
      RECT  270.92 0.8975 273.365 1.3125 ;
      RECT  273.78 0.8975 276.225 1.3125 ;
      RECT  276.64 0.8975 279.085 1.3125 ;
      RECT  279.5 0.8975 281.945 1.3125 ;
      RECT  282.36 0.8975 284.805 1.3125 ;
      RECT  285.22 0.8975 287.665 1.3125 ;
      RECT  288.08 0.8975 290.525 1.3125 ;
      RECT  290.94 0.8975 293.385 1.3125 ;
      RECT  293.8 0.8975 296.245 1.3125 ;
      RECT  296.66 0.8975 299.105 1.3125 ;
      RECT  299.52 0.8975 301.965 1.3125 ;
      RECT  302.38 0.8975 304.825 1.3125 ;
      RECT  305.24 0.8975 307.685 1.3125 ;
      RECT  308.1 0.8975 310.545 1.3125 ;
      RECT  310.96 0.8975 313.405 1.3125 ;
      RECT  313.82 0.8975 316.265 1.3125 ;
      RECT  316.68 0.8975 319.125 1.3125 ;
      RECT  319.54 0.8975 321.985 1.3125 ;
      RECT  322.4 0.8975 324.845 1.3125 ;
      RECT  325.26 0.8975 327.705 1.3125 ;
      RECT  328.12 0.8975 330.565 1.3125 ;
      RECT  330.98 0.8975 333.425 1.3125 ;
      RECT  333.84 0.8975 336.285 1.3125 ;
      RECT  336.7 0.8975 339.145 1.3125 ;
      RECT  339.56 0.8975 342.005 1.3125 ;
      RECT  342.42 0.8975 344.865 1.3125 ;
      RECT  345.28 0.8975 347.725 1.3125 ;
      RECT  348.14 0.8975 350.585 1.3125 ;
      RECT  351.0 0.8975 353.445 1.3125 ;
      RECT  353.86 0.8975 356.305 1.3125 ;
      RECT  356.72 0.8975 359.165 1.3125 ;
      RECT  359.58 0.8975 362.025 1.3125 ;
      RECT  362.44 0.8975 364.885 1.3125 ;
      RECT  365.3 0.8975 367.745 1.3125 ;
      RECT  368.16 0.8975 370.605 1.3125 ;
      RECT  371.02 0.8975 373.465 1.3125 ;
      RECT  373.88 0.8975 376.325 1.3125 ;
      RECT  376.74 0.8975 379.185 1.3125 ;
      RECT  379.6 0.8975 382.045 1.3125 ;
      RECT  382.46 0.8975 384.905 1.3125 ;
      RECT  385.32 0.8975 387.765 1.3125 ;
      RECT  388.18 0.8975 390.625 1.3125 ;
      RECT  391.04 0.8975 393.485 1.3125 ;
      RECT  393.9 0.8975 396.345 1.3125 ;
      RECT  396.76 0.8975 399.205 1.3125 ;
      RECT  399.62 0.8975 402.065 1.3125 ;
      RECT  402.48 0.8975 404.925 1.3125 ;
      RECT  405.34 0.8975 407.785 1.3125 ;
      RECT  408.2 0.8975 410.645 1.3125 ;
      RECT  411.06 0.8975 413.505 1.3125 ;
      RECT  413.92 0.8975 416.365 1.3125 ;
      RECT  416.78 0.8975 419.225 1.3125 ;
      RECT  419.64 0.8975 422.085 1.3125 ;
      RECT  422.5 0.8975 424.945 1.3125 ;
      RECT  425.36 0.8975 427.805 1.3125 ;
      RECT  428.22 0.8975 430.665 1.3125 ;
      RECT  431.08 0.8975 433.525 1.3125 ;
      RECT  433.94 0.8975 436.385 1.3125 ;
      RECT  436.8 0.8975 439.245 1.3125 ;
      RECT  439.66 0.8975 442.105 1.3125 ;
      RECT  442.52 0.8975 444.965 1.3125 ;
      RECT  445.38 0.8975 447.825 1.3125 ;
      RECT  448.24 0.8975 450.685 1.3125 ;
      RECT  451.1 0.8975 453.545 1.3125 ;
      RECT  453.96 0.8975 456.405 1.3125 ;
      RECT  456.82 0.8975 459.265 1.3125 ;
      RECT  459.68 0.8975 462.125 1.3125 ;
      RECT  462.54 0.8975 464.985 1.3125 ;
      RECT  465.4 0.8975 467.845 1.3125 ;
      RECT  468.26 0.8975 470.705 1.3125 ;
      RECT  471.12 0.8975 473.565 1.3125 ;
      RECT  473.98 0.8975 476.425 1.3125 ;
      RECT  476.84 0.8975 479.285 1.3125 ;
      RECT  479.7 0.8975 482.145 1.3125 ;
      RECT  482.56 0.8975 485.005 1.3125 ;
      RECT  485.42 0.8975 487.865 1.3125 ;
      RECT  488.28 0.8975 490.725 1.3125 ;
      RECT  491.14 0.8975 493.585 1.3125 ;
      RECT  494.0 0.8975 496.445 1.3125 ;
      RECT  496.86 0.8975 499.305 1.3125 ;
      RECT  499.72 0.8975 502.165 1.3125 ;
      RECT  502.58 0.8975 505.025 1.3125 ;
      RECT  505.44 0.8975 507.885 1.3125 ;
      RECT  508.3 0.8975 510.745 1.3125 ;
      RECT  511.16 0.8975 513.605 1.3125 ;
      RECT  514.02 0.8975 516.465 1.3125 ;
      RECT  516.88 0.8975 519.325 1.3125 ;
      RECT  519.74 0.8975 522.185 1.3125 ;
      RECT  522.6 0.8975 525.045 1.3125 ;
      RECT  525.46 0.8975 527.905 1.3125 ;
      RECT  528.32 0.8975 530.765 1.3125 ;
      RECT  531.18 0.8975 533.625 1.3125 ;
      RECT  534.04 0.8975 536.485 1.3125 ;
      RECT  536.9 0.8975 539.345 1.3125 ;
      RECT  539.76 0.8975 542.205 1.3125 ;
      RECT  542.62 0.8975 545.065 1.3125 ;
      RECT  545.48 0.8975 547.925 1.3125 ;
      RECT  548.34 0.8975 550.785 1.3125 ;
      RECT  551.2 0.8975 553.645 1.3125 ;
      RECT  554.06 0.8975 556.505 1.3125 ;
      RECT  556.92 0.8975 559.365 1.3125 ;
      RECT  559.78 0.8975 562.225 1.3125 ;
      RECT  562.64 0.8975 565.085 1.3125 ;
      RECT  565.5 0.8975 567.945 1.3125 ;
      RECT  568.36 0.8975 570.805 1.3125 ;
      RECT  571.22 0.8975 573.665 1.3125 ;
      RECT  574.08 0.8975 576.525 1.3125 ;
      RECT  576.94 0.8975 579.385 1.3125 ;
      RECT  579.8 0.8975 582.245 1.3125 ;
      RECT  582.66 0.8975 585.105 1.3125 ;
      RECT  585.52 0.8975 587.965 1.3125 ;
      RECT  588.38 0.8975 590.825 1.3125 ;
      RECT  591.24 0.8975 593.685 1.3125 ;
      RECT  594.1 0.8975 596.545 1.3125 ;
      RECT  596.96 0.8975 599.405 1.3125 ;
      RECT  599.82 0.8975 602.265 1.3125 ;
      RECT  602.68 0.8975 605.125 1.3125 ;
      RECT  605.54 0.8975 607.985 1.3125 ;
      RECT  608.4 0.8975 610.845 1.3125 ;
      RECT  611.26 0.8975 613.705 1.3125 ;
      RECT  614.12 0.8975 616.565 1.3125 ;
      RECT  616.98 0.8975 619.425 1.3125 ;
      RECT  619.84 0.8975 622.285 1.3125 ;
      RECT  622.7 0.8975 625.145 1.3125 ;
      RECT  625.56 0.8975 628.005 1.3125 ;
      RECT  628.42 0.8975 630.865 1.3125 ;
      RECT  631.28 0.8975 633.725 1.3125 ;
      RECT  634.14 0.8975 636.585 1.3125 ;
      RECT  637.0 0.8975 639.23 1.3125 ;
      RECT  0.14 86.18 50.285 86.595 ;
      RECT  0.14 86.595 50.285 152.225 ;
      RECT  50.285 1.3125 50.7 86.18 ;
      RECT  50.7 86.18 90.325 86.595 ;
      RECT  50.7 86.595 90.325 152.225 ;
      RECT  50.285 86.595 50.7 88.91 ;
      RECT  50.285 89.325 50.7 91.12 ;
      RECT  50.285 91.535 50.7 93.85 ;
      RECT  50.285 94.265 50.7 96.06 ;
      RECT  50.285 96.475 50.7 98.79 ;
      RECT  50.285 99.205 50.7 152.225 ;
      RECT  0.14 1.3125 0.145 41.46 ;
      RECT  0.14 41.46 0.145 41.875 ;
      RECT  0.14 41.875 0.145 86.18 ;
      RECT  0.145 1.3125 0.56 41.46 ;
      RECT  0.56 1.3125 50.285 41.46 ;
      RECT  0.145 41.875 0.56 44.19 ;
      RECT  0.145 44.605 0.56 86.18 ;
      RECT  0.56 41.46 6.3875 41.545 ;
      RECT  0.56 41.545 6.3875 41.875 ;
      RECT  6.3875 41.46 6.8025 41.545 ;
      RECT  6.8025 41.46 50.285 41.545 ;
      RECT  6.8025 41.545 50.285 41.875 ;
      RECT  0.56 41.875 6.3875 41.96 ;
      RECT  0.56 41.96 6.3875 86.18 ;
      RECT  6.3875 41.96 6.8025 86.18 ;
      RECT  6.8025 41.875 50.285 41.96 ;
      RECT  6.8025 41.96 50.285 86.18 ;
      RECT  0.14 0.8975 56.005 1.3125 ;
      RECT  56.42 0.8975 58.865 1.3125 ;
      RECT  59.28 0.8975 61.725 1.3125 ;
      RECT  62.14 0.8975 64.585 1.3125 ;
      RECT  65.0 0.8975 67.445 1.3125 ;
      RECT  67.86 0.8975 70.305 1.3125 ;
      RECT  70.72 0.8975 73.165 1.3125 ;
      RECT  73.58 0.8975 76.025 1.3125 ;
      RECT  76.44 0.8975 78.885 1.3125 ;
      RECT  79.3 0.8975 81.745 1.3125 ;
      RECT  82.16 0.8975 84.605 1.3125 ;
      RECT  85.02 0.8975 87.465 1.3125 ;
      RECT  87.88 0.8975 90.325 1.3125 ;
      RECT  50.7 1.3125 76.815 52.6025 ;
      RECT  50.7 52.6025 76.815 53.0175 ;
      RECT  50.7 53.0175 76.815 86.18 ;
      RECT  76.815 1.3125 77.23 52.6025 ;
      RECT  76.815 53.0175 77.23 86.18 ;
      RECT  77.23 1.3125 90.325 52.6025 ;
      RECT  77.23 53.0175 90.325 86.18 ;
      RECT  77.23 52.6025 77.52 53.0175 ;
      RECT  77.935 52.6025 78.225 53.0175 ;
      RECT  78.64 52.6025 78.93 53.0175 ;
      RECT  79.345 52.6025 79.635 53.0175 ;
      RECT  80.05 52.6025 80.34 53.0175 ;
      RECT  80.755 52.6025 81.045 53.0175 ;
      RECT  81.46 52.6025 81.75 53.0175 ;
      RECT  82.165 52.6025 82.455 53.0175 ;
      RECT  82.87 52.6025 83.16 53.0175 ;
      RECT  83.575 52.6025 83.865 53.0175 ;
      RECT  84.28 52.6025 84.57 53.0175 ;
      RECT  84.985 52.6025 85.275 53.0175 ;
      RECT  85.69 52.6025 85.98 53.0175 ;
      RECT  86.395 52.6025 86.685 53.0175 ;
      RECT  87.1 52.6025 87.39 53.0175 ;
      RECT  87.805 52.6025 88.095 53.0175 ;
      RECT  88.51 52.6025 88.8 53.0175 ;
      RECT  89.215 52.6025 89.505 53.0175 ;
      RECT  90.325 1.3125 90.625 52.6025 ;
      RECT  90.325 53.0175 90.625 152.225 ;
      RECT  90.625 1.3125 90.74 52.6025 ;
      RECT  90.625 52.6025 90.74 53.0175 ;
      RECT  90.625 53.0175 90.74 152.225 ;
      RECT  89.92 52.6025 90.21 53.0175 ;
      RECT  90.74 1.3125 90.915 52.6025 ;
      RECT  90.74 52.6025 90.915 53.0175 ;
      RECT  90.74 53.0175 90.915 152.225 ;
      RECT  90.915 1.3125 91.33 52.6025 ;
      RECT  90.915 53.0175 91.33 152.225 ;
      RECT  91.33 1.3125 639.23 52.6025 ;
      RECT  91.33 53.0175 639.23 152.225 ;
      RECT  91.33 52.6025 91.62 53.0175 ;
      RECT  92.035 52.6025 92.325 53.0175 ;
      RECT  92.74 52.6025 93.03 53.0175 ;
      RECT  93.445 52.6025 93.735 53.0175 ;
      RECT  94.15 52.6025 94.44 53.0175 ;
      RECT  94.855 52.6025 95.145 53.0175 ;
      RECT  95.56 52.6025 95.85 53.0175 ;
      RECT  96.265 52.6025 96.555 53.0175 ;
      RECT  96.97 52.6025 97.26 53.0175 ;
      RECT  97.675 52.6025 97.965 53.0175 ;
      RECT  98.38 52.6025 98.67 53.0175 ;
      RECT  99.085 52.6025 99.375 53.0175 ;
      RECT  99.79 52.6025 100.08 53.0175 ;
      RECT  100.495 52.6025 100.785 53.0175 ;
      RECT  101.2 52.6025 101.49 53.0175 ;
      RECT  101.905 52.6025 102.195 53.0175 ;
      RECT  102.61 52.6025 102.9 53.0175 ;
      RECT  103.315 52.6025 103.605 53.0175 ;
      RECT  104.02 52.6025 104.31 53.0175 ;
      RECT  104.725 52.6025 105.015 53.0175 ;
      RECT  105.43 52.6025 105.72 53.0175 ;
      RECT  106.135 52.6025 106.425 53.0175 ;
      RECT  106.84 52.6025 107.13 53.0175 ;
      RECT  107.545 52.6025 107.835 53.0175 ;
      RECT  108.25 52.6025 108.54 53.0175 ;
      RECT  108.955 52.6025 109.245 53.0175 ;
      RECT  109.66 52.6025 109.95 53.0175 ;
      RECT  110.365 52.6025 110.655 53.0175 ;
      RECT  111.07 52.6025 111.36 53.0175 ;
      RECT  111.775 52.6025 112.065 53.0175 ;
      RECT  112.48 52.6025 112.77 53.0175 ;
      RECT  113.185 52.6025 113.475 53.0175 ;
      RECT  113.89 52.6025 114.18 53.0175 ;
      RECT  114.595 52.6025 114.885 53.0175 ;
      RECT  115.3 52.6025 115.59 53.0175 ;
      RECT  116.005 52.6025 116.295 53.0175 ;
      RECT  116.71 52.6025 117.0 53.0175 ;
      RECT  117.415 52.6025 117.705 53.0175 ;
      RECT  118.12 52.6025 118.41 53.0175 ;
      RECT  118.825 52.6025 119.115 53.0175 ;
      RECT  119.53 52.6025 119.82 53.0175 ;
      RECT  120.235 52.6025 120.525 53.0175 ;
      RECT  120.94 52.6025 121.23 53.0175 ;
      RECT  121.645 52.6025 121.935 53.0175 ;
      RECT  122.35 52.6025 122.64 53.0175 ;
      RECT  123.055 52.6025 123.345 53.0175 ;
      RECT  123.76 52.6025 124.05 53.0175 ;
      RECT  124.465 52.6025 124.755 53.0175 ;
      RECT  125.17 52.6025 125.46 53.0175 ;
      RECT  125.875 52.6025 126.165 53.0175 ;
      RECT  126.58 52.6025 126.87 53.0175 ;
      RECT  127.285 52.6025 127.575 53.0175 ;
      RECT  127.99 52.6025 128.28 53.0175 ;
      RECT  128.695 52.6025 128.985 53.0175 ;
      RECT  129.4 52.6025 129.69 53.0175 ;
      RECT  130.105 52.6025 130.395 53.0175 ;
      RECT  130.81 52.6025 131.1 53.0175 ;
      RECT  131.515 52.6025 131.805 53.0175 ;
      RECT  132.22 52.6025 132.51 53.0175 ;
      RECT  132.925 52.6025 133.215 53.0175 ;
      RECT  133.63 52.6025 133.92 53.0175 ;
      RECT  134.335 52.6025 134.625 53.0175 ;
      RECT  135.04 52.6025 135.33 53.0175 ;
      RECT  135.745 52.6025 136.035 53.0175 ;
      RECT  136.45 52.6025 136.74 53.0175 ;
      RECT  137.155 52.6025 137.445 53.0175 ;
      RECT  137.86 52.6025 138.15 53.0175 ;
      RECT  138.565 52.6025 138.855 53.0175 ;
      RECT  139.27 52.6025 139.56 53.0175 ;
      RECT  139.975 52.6025 140.265 53.0175 ;
      RECT  140.68 52.6025 140.97 53.0175 ;
      RECT  141.385 52.6025 141.675 53.0175 ;
      RECT  142.09 52.6025 142.38 53.0175 ;
      RECT  142.795 52.6025 143.085 53.0175 ;
      RECT  143.5 52.6025 143.79 53.0175 ;
      RECT  144.205 52.6025 144.495 53.0175 ;
      RECT  144.91 52.6025 145.2 53.0175 ;
      RECT  145.615 52.6025 145.905 53.0175 ;
      RECT  146.32 52.6025 146.61 53.0175 ;
      RECT  147.025 52.6025 147.315 53.0175 ;
      RECT  147.73 52.6025 148.02 53.0175 ;
      RECT  148.435 52.6025 148.725 53.0175 ;
      RECT  149.14 52.6025 149.43 53.0175 ;
      RECT  149.845 52.6025 150.135 53.0175 ;
      RECT  150.55 52.6025 150.84 53.0175 ;
      RECT  151.255 52.6025 151.545 53.0175 ;
      RECT  151.96 52.6025 152.25 53.0175 ;
      RECT  152.665 52.6025 152.955 53.0175 ;
      RECT  153.37 52.6025 153.66 53.0175 ;
      RECT  154.075 52.6025 154.365 53.0175 ;
      RECT  154.78 52.6025 155.07 53.0175 ;
      RECT  155.485 52.6025 155.775 53.0175 ;
      RECT  156.19 52.6025 156.48 53.0175 ;
      RECT  156.895 52.6025 157.185 53.0175 ;
      RECT  157.6 52.6025 157.89 53.0175 ;
      RECT  158.305 52.6025 158.595 53.0175 ;
      RECT  159.01 52.6025 159.3 53.0175 ;
      RECT  159.715 52.6025 160.005 53.0175 ;
      RECT  160.42 52.6025 160.71 53.0175 ;
      RECT  161.125 52.6025 161.415 53.0175 ;
      RECT  161.83 52.6025 162.12 53.0175 ;
      RECT  162.535 52.6025 162.825 53.0175 ;
      RECT  163.24 52.6025 163.53 53.0175 ;
      RECT  163.945 52.6025 164.235 53.0175 ;
      RECT  164.65 52.6025 164.94 53.0175 ;
      RECT  165.355 52.6025 165.645 53.0175 ;
      RECT  166.06 52.6025 166.35 53.0175 ;
      RECT  166.765 52.6025 167.055 53.0175 ;
      RECT  167.47 52.6025 167.76 53.0175 ;
      RECT  168.175 52.6025 168.465 53.0175 ;
      RECT  168.88 52.6025 169.17 53.0175 ;
      RECT  169.585 52.6025 169.875 53.0175 ;
      RECT  170.29 52.6025 170.58 53.0175 ;
      RECT  170.995 52.6025 171.285 53.0175 ;
      RECT  171.7 52.6025 171.99 53.0175 ;
      RECT  172.405 52.6025 172.695 53.0175 ;
      RECT  173.11 52.6025 173.4 53.0175 ;
      RECT  173.815 52.6025 174.105 53.0175 ;
      RECT  174.52 52.6025 174.81 53.0175 ;
      RECT  175.225 52.6025 175.515 53.0175 ;
      RECT  175.93 52.6025 176.22 53.0175 ;
      RECT  176.635 52.6025 176.925 53.0175 ;
      RECT  177.34 52.6025 177.63 53.0175 ;
      RECT  178.045 52.6025 178.335 53.0175 ;
      RECT  178.75 52.6025 179.04 53.0175 ;
      RECT  179.455 52.6025 179.745 53.0175 ;
      RECT  180.16 52.6025 180.45 53.0175 ;
      RECT  180.865 52.6025 181.155 53.0175 ;
      RECT  181.57 52.6025 181.86 53.0175 ;
      RECT  182.275 52.6025 182.565 53.0175 ;
      RECT  182.98 52.6025 183.27 53.0175 ;
      RECT  183.685 52.6025 183.975 53.0175 ;
      RECT  184.39 52.6025 184.68 53.0175 ;
      RECT  185.095 52.6025 185.385 53.0175 ;
      RECT  185.8 52.6025 186.09 53.0175 ;
      RECT  186.505 52.6025 186.795 53.0175 ;
      RECT  187.21 52.6025 187.5 53.0175 ;
      RECT  187.915 52.6025 188.205 53.0175 ;
      RECT  188.62 52.6025 188.91 53.0175 ;
      RECT  189.325 52.6025 189.615 53.0175 ;
      RECT  190.03 52.6025 190.32 53.0175 ;
      RECT  190.735 52.6025 191.025 53.0175 ;
      RECT  191.44 52.6025 191.73 53.0175 ;
      RECT  192.145 52.6025 192.435 53.0175 ;
      RECT  192.85 52.6025 193.14 53.0175 ;
      RECT  193.555 52.6025 193.845 53.0175 ;
      RECT  194.26 52.6025 194.55 53.0175 ;
      RECT  194.965 52.6025 195.255 53.0175 ;
      RECT  195.67 52.6025 195.96 53.0175 ;
      RECT  196.375 52.6025 196.665 53.0175 ;
      RECT  197.08 52.6025 197.37 53.0175 ;
      RECT  197.785 52.6025 198.075 53.0175 ;
      RECT  198.49 52.6025 198.78 53.0175 ;
      RECT  199.195 52.6025 199.485 53.0175 ;
      RECT  199.9 52.6025 200.19 53.0175 ;
      RECT  200.605 52.6025 200.895 53.0175 ;
      RECT  201.31 52.6025 201.6 53.0175 ;
      RECT  202.015 52.6025 202.305 53.0175 ;
      RECT  202.72 52.6025 203.01 53.0175 ;
      RECT  203.425 52.6025 203.715 53.0175 ;
      RECT  204.13 52.6025 204.42 53.0175 ;
      RECT  204.835 52.6025 205.125 53.0175 ;
      RECT  205.54 52.6025 205.83 53.0175 ;
      RECT  206.245 52.6025 206.535 53.0175 ;
      RECT  206.95 52.6025 207.24 53.0175 ;
      RECT  207.655 52.6025 207.945 53.0175 ;
      RECT  208.36 52.6025 208.65 53.0175 ;
      RECT  209.065 52.6025 209.355 53.0175 ;
      RECT  209.77 52.6025 210.06 53.0175 ;
      RECT  210.475 52.6025 210.765 53.0175 ;
      RECT  211.18 52.6025 211.47 53.0175 ;
      RECT  211.885 52.6025 639.23 53.0175 ;
   LAYER  metal4 ;
      RECT  0.14 0.14 639.23 152.225 ;
   END
END    sram_act_buf_1rw0r0w_192_64_freepdk45
END    LIBRARY
